VERSION 5.7 ;
BUSBITCHARS "[]" ;
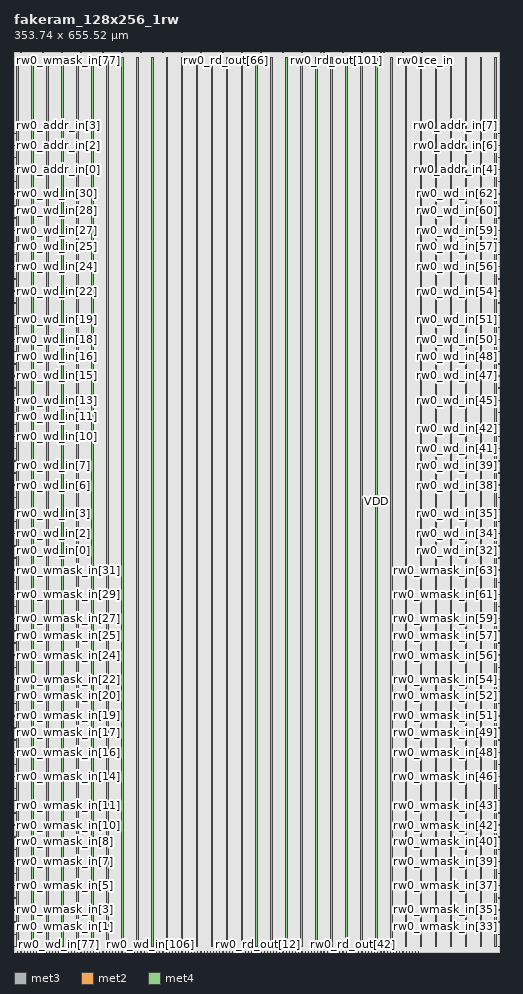
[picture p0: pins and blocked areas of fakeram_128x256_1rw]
MACRO fakeram_128x256_1rw
  FOREIGN fakeram_128x256_1rw 0 0 ;
  SYMMETRY X Y R90 ;
  SIZE 353.740 BY 655.520 ;
  CLASS BLOCK ;
  PIN rw0_wmask_in[0]
    DIRECTION INPUT ;
    USE SIGNAL ;
    SHAPE ABUTMENT ;
    PORT
      LAYER met3 ;
      RECT 0.000 3.930 0.900 4.230 ;
    END
  END rw0_wmask_in[0]
  PIN rw0_wmask_in[1]
    DIRECTION INPUT ;
    USE SIGNAL ;
    SHAPE ABUTMENT ;
    PORT
      LAYER met3 ;
      RECT 0.000 12.770 0.900 13.070 ;
    END
  END rw0_wmask_in[1]
  PIN rw0_wmask_in[2]
    DIRECTION INPUT ;
    USE SIGNAL ;
    SHAPE ABUTMENT ;
    PORT
      LAYER met3 ;
      RECT 0.000 21.610 0.900 21.910 ;
    END
  END rw0_wmask_in[2]
  PIN rw0_wmask_in[3]
    DIRECTION INPUT ;
    USE SIGNAL ;
    SHAPE ABUTMENT ;
    PORT
      LAYER met3 ;
      RECT 0.000 30.450 0.900 30.750 ;
    END
  END rw0_wmask_in[3]
  PIN rw0_wmask_in[4]
    DIRECTION INPUT ;
    USE SIGNAL ;
    SHAPE ABUTMENT ;
    PORT
      LAYER met3 ;
      RECT 0.000 39.290 0.900 39.590 ;
    END
  END rw0_wmask_in[4]
  PIN rw0_wmask_in[5]
    DIRECTION INPUT ;
    USE SIGNAL ;
    SHAPE ABUTMENT ;
    PORT
      LAYER met3 ;
      RECT 0.000 48.130 0.900 48.430 ;
    END
  END rw0_wmask_in[5]
  PIN rw0_wmask_in[6]
    DIRECTION INPUT ;
    USE SIGNAL ;
    SHAPE ABUTMENT ;
    PORT
      LAYER met3 ;
      RECT 0.000 56.970 0.900 57.270 ;
    END
  END rw0_wmask_in[6]
  PIN rw0_wmask_in[7]
    DIRECTION INPUT ;
    USE SIGNAL ;
    SHAPE ABUTMENT ;
    PORT
      LAYER met3 ;
      RECT 0.000 65.810 0.900 66.110 ;
    END
  END rw0_wmask_in[7]
  PIN rw0_wmask_in[8]
    DIRECTION INPUT ;
    USE SIGNAL ;
    SHAPE ABUTMENT ;
    PORT
      LAYER met3 ;
      RECT 0.000 74.650 0.900 74.950 ;
    END
  END rw0_wmask_in[8]
  PIN rw0_wmask_in[9]
    DIRECTION INPUT ;
    USE SIGNAL ;
    SHAPE ABUTMENT ;
    PORT
      LAYER met3 ;
      RECT 0.000 83.490 0.900 83.790 ;
    END
  END rw0_wmask_in[9]
  PIN rw0_wmask_in[10]
    DIRECTION INPUT ;
    USE SIGNAL ;
    SHAPE ABUTMENT ;
    PORT
      LAYER met3 ;
      RECT 0.000 92.330 0.900 92.630 ;
    END
  END rw0_wmask_in[10]
  PIN rw0_wmask_in[11]
    DIRECTION INPUT ;
    USE SIGNAL ;
    SHAPE ABUTMENT ;
    PORT
      LAYER met3 ;
      RECT 0.000 101.170 0.900 101.470 ;
    END
  END rw0_wmask_in[11]
  PIN rw0_wmask_in[12]
    DIRECTION INPUT ;
    USE SIGNAL ;
    SHAPE ABUTMENT ;
    PORT
      LAYER met3 ;
      RECT 0.000 110.010 0.900 110.310 ;
    END
  END rw0_wmask_in[12]
  PIN rw0_wmask_in[13]
    DIRECTION INPUT ;
    USE SIGNAL ;
    SHAPE ABUTMENT ;
    PORT
      LAYER met3 ;
      RECT 0.000 118.850 0.900 119.150 ;
    END
  END rw0_wmask_in[13]
  PIN rw0_wmask_in[14]
    DIRECTION INPUT ;
    USE SIGNAL ;
    SHAPE ABUTMENT ;
    PORT
      LAYER met3 ;
      RECT 0.000 127.690 0.900 127.990 ;
    END
  END rw0_wmask_in[14]
  PIN rw0_wmask_in[15]
    DIRECTION INPUT ;
    USE SIGNAL ;
    SHAPE ABUTMENT ;
    PORT
      LAYER met3 ;
      RECT 0.000 136.530 0.900 136.830 ;
    END
  END rw0_wmask_in[15]
  PIN rw0_wmask_in[16]
    DIRECTION INPUT ;
    USE SIGNAL ;
    SHAPE ABUTMENT ;
    PORT
      LAYER met3 ;
      RECT 0.000 145.370 0.900 145.670 ;
    END
  END rw0_wmask_in[16]
  PIN rw0_wmask_in[17]
    DIRECTION INPUT ;
    USE SIGNAL ;
    SHAPE ABUTMENT ;
    PORT
      LAYER met3 ;
      RECT 0.000 154.210 0.900 154.510 ;
    END
  END rw0_wmask_in[17]
  PIN rw0_wmask_in[18]
    DIRECTION INPUT ;
    USE SIGNAL ;
    SHAPE ABUTMENT ;
    PORT
      LAYER met3 ;
      RECT 0.000 163.050 0.900 163.350 ;
    END
  END rw0_wmask_in[18]
  PIN rw0_wmask_in[19]
    DIRECTION INPUT ;
    USE SIGNAL ;
    SHAPE ABUTMENT ;
    PORT
      LAYER met3 ;
      RECT 0.000 171.890 0.900 172.190 ;
    END
  END rw0_wmask_in[19]
  PIN rw0_wmask_in[20]
    DIRECTION INPUT ;
    USE SIGNAL ;
    SHAPE ABUTMENT ;
    PORT
      LAYER met3 ;
      RECT 0.000 180.730 0.900 181.030 ;
    END
  END rw0_wmask_in[20]
  PIN rw0_wmask_in[21]
    DIRECTION INPUT ;
    USE SIGNAL ;
    SHAPE ABUTMENT ;
    PORT
      LAYER met3 ;
      RECT 0.000 189.570 0.900 189.870 ;
    END
  END rw0_wmask_in[21]
  PIN rw0_wmask_in[22]
    DIRECTION INPUT ;
    USE SIGNAL ;
    SHAPE ABUTMENT ;
    PORT
      LAYER met3 ;
      RECT 0.000 198.410 0.900 198.710 ;
    END
  END rw0_wmask_in[22]
  PIN rw0_wmask_in[23]
    DIRECTION INPUT ;
    USE SIGNAL ;
    SHAPE ABUTMENT ;
    PORT
      LAYER met3 ;
      RECT 0.000 207.250 0.900 207.550 ;
    END
  END rw0_wmask_in[23]
  PIN rw0_wmask_in[24]
    DIRECTION INPUT ;
    USE SIGNAL ;
    SHAPE ABUTMENT ;
    PORT
      LAYER met3 ;
      RECT 0.000 216.090 0.900 216.390 ;
    END
  END rw0_wmask_in[24]
  PIN rw0_wmask_in[25]
    DIRECTION INPUT ;
    USE SIGNAL ;
    SHAPE ABUTMENT ;
    PORT
      LAYER met3 ;
      RECT 0.000 224.930 0.900 225.230 ;
    END
  END rw0_wmask_in[25]
  PIN rw0_wmask_in[26]
    DIRECTION INPUT ;
    USE SIGNAL ;
    SHAPE ABUTMENT ;
    PORT
      LAYER met3 ;
      RECT 0.000 233.770 0.900 234.070 ;
    END
  END rw0_wmask_in[26]
  PIN rw0_wmask_in[27]
    DIRECTION INPUT ;
    USE SIGNAL ;
    SHAPE ABUTMENT ;
    PORT
      LAYER met3 ;
      RECT 0.000 242.610 0.900 242.910 ;
    END
  END rw0_wmask_in[27]
  PIN rw0_wmask_in[28]
    DIRECTION INPUT ;
    USE SIGNAL ;
    SHAPE ABUTMENT ;
    PORT
      LAYER met3 ;
      RECT 0.000 251.450 0.900 251.750 ;
    END
  END rw0_wmask_in[28]
  PIN rw0_wmask_in[29]
    DIRECTION INPUT ;
    USE SIGNAL ;
    SHAPE ABUTMENT ;
    PORT
      LAYER met3 ;
      RECT 0.000 260.290 0.900 260.590 ;
    END
  END rw0_wmask_in[29]
  PIN rw0_wmask_in[30]
    DIRECTION INPUT ;
    USE SIGNAL ;
    SHAPE ABUTMENT ;
    PORT
      LAYER met3 ;
      RECT 0.000 269.130 0.900 269.430 ;
    END
  END rw0_wmask_in[30]
  PIN rw0_wmask_in[31]
    DIRECTION INPUT ;
    USE SIGNAL ;
    SHAPE ABUTMENT ;
    PORT
      LAYER met3 ;
      RECT 0.000 277.970 0.900 278.270 ;
    END
  END rw0_wmask_in[31]
  PIN rw0_wmask_in[32]
    DIRECTION INPUT ;
    USE SIGNAL ;
    SHAPE ABUTMENT ;
    PORT
      LAYER met3 ;
      RECT 352.840 3.930 353.740 4.230 ;
    END
  END rw0_wmask_in[32]
  PIN rw0_wmask_in[33]
    DIRECTION INPUT ;
    USE SIGNAL ;
    SHAPE ABUTMENT ;
    PORT
      LAYER met3 ;
      RECT 352.840 12.770 353.740 13.070 ;
    END
  END rw0_wmask_in[33]
  PIN rw0_wmask_in[34]
    DIRECTION INPUT ;
    USE SIGNAL ;
    SHAPE ABUTMENT ;
    PORT
      LAYER met3 ;
      RECT 352.840 21.610 353.740 21.910 ;
    END
  END rw0_wmask_in[34]
  PIN rw0_wmask_in[35]
    DIRECTION INPUT ;
    USE SIGNAL ;
    SHAPE ABUTMENT ;
    PORT
      LAYER met3 ;
      RECT 352.840 30.450 353.740 30.750 ;
    END
  END rw0_wmask_in[35]
  PIN rw0_wmask_in[36]
    DIRECTION INPUT ;
    USE SIGNAL ;
    SHAPE ABUTMENT ;
    PORT
      LAYER met3 ;
      RECT 352.840 39.290 353.740 39.590 ;
    END
  END rw0_wmask_in[36]
  PIN rw0_wmask_in[37]
    DIRECTION INPUT ;
    USE SIGNAL ;
    SHAPE ABUTMENT ;
    PORT
      LAYER met3 ;
      RECT 352.840 48.130 353.740 48.430 ;
    END
  END rw0_wmask_in[37]
  PIN rw0_wmask_in[38]
    DIRECTION INPUT ;
    USE SIGNAL ;
    SHAPE ABUTMENT ;
    PORT
      LAYER met3 ;
      RECT 352.840 56.970 353.740 57.270 ;
    END
  END rw0_wmask_in[38]
  PIN rw0_wmask_in[39]
    DIRECTION INPUT ;
    USE SIGNAL ;
    SHAPE ABUTMENT ;
    PORT
      LAYER met3 ;
      RECT 352.840 65.810 353.740 66.110 ;
    END
  END rw0_wmask_in[39]
  PIN rw0_wmask_in[40]
    DIRECTION INPUT ;
    USE SIGNAL ;
    SHAPE ABUTMENT ;
    PORT
      LAYER met3 ;
      RECT 352.840 74.650 353.740 74.950 ;
    END
  END rw0_wmask_in[40]
  PIN rw0_wmask_in[41]
    DIRECTION INPUT ;
    USE SIGNAL ;
    SHAPE ABUTMENT ;
    PORT
      LAYER met3 ;
      RECT 352.840 83.490 353.740 83.790 ;
    END
  END rw0_wmask_in[41]
  PIN rw0_wmask_in[42]
    DIRECTION INPUT ;
    USE SIGNAL ;
    SHAPE ABUTMENT ;
    PORT
      LAYER met3 ;
      RECT 352.840 92.330 353.740 92.630 ;
    END
  END rw0_wmask_in[42]
  PIN rw0_wmask_in[43]
    DIRECTION INPUT ;
    USE SIGNAL ;
    SHAPE ABUTMENT ;
    PORT
      LAYER met3 ;
      RECT 352.840 101.170 353.740 101.470 ;
    END
  END rw0_wmask_in[43]
  PIN rw0_wmask_in[44]
    DIRECTION INPUT ;
    USE SIGNAL ;
    SHAPE ABUTMENT ;
    PORT
      LAYER met3 ;
      RECT 352.840 110.010 353.740 110.310 ;
    END
  END rw0_wmask_in[44]
  PIN rw0_wmask_in[45]
    DIRECTION INPUT ;
    USE SIGNAL ;
    SHAPE ABUTMENT ;
    PORT
      LAYER met3 ;
      RECT 352.840 118.850 353.740 119.150 ;
    END
  END rw0_wmask_in[45]
  PIN rw0_wmask_in[46]
    DIRECTION INPUT ;
    USE SIGNAL ;
    SHAPE ABUTMENT ;
    PORT
      LAYER met3 ;
      RECT 352.840 127.690 353.740 127.990 ;
    END
  END rw0_wmask_in[46]
  PIN rw0_wmask_in[47]
    DIRECTION INPUT ;
    USE SIGNAL ;
    SHAPE ABUTMENT ;
    PORT
      LAYER met3 ;
      RECT 352.840 136.530 353.740 136.830 ;
    END
  END rw0_wmask_in[47]
  PIN rw0_wmask_in[48]
    DIRECTION INPUT ;
    USE SIGNAL ;
    SHAPE ABUTMENT ;
    PORT
      LAYER met3 ;
      RECT 352.840 145.370 353.740 145.670 ;
    END
  END rw0_wmask_in[48]
  PIN rw0_wmask_in[49]
    DIRECTION INPUT ;
    USE SIGNAL ;
    SHAPE ABUTMENT ;
    PORT
      LAYER met3 ;
      RECT 352.840 154.210 353.740 154.510 ;
    END
  END rw0_wmask_in[49]
  PIN rw0_wmask_in[50]
    DIRECTION INPUT ;
    USE SIGNAL ;
    SHAPE ABUTMENT ;
    PORT
      LAYER met3 ;
      RECT 352.840 163.050 353.740 163.350 ;
    END
  END rw0_wmask_in[50]
  PIN rw0_wmask_in[51]
    DIRECTION INPUT ;
    USE SIGNAL ;
    SHAPE ABUTMENT ;
    PORT
      LAYER met3 ;
      RECT 352.840 171.890 353.740 172.190 ;
    END
  END rw0_wmask_in[51]
  PIN rw0_wmask_in[52]
    DIRECTION INPUT ;
    USE SIGNAL ;
    SHAPE ABUTMENT ;
    PORT
      LAYER met3 ;
      RECT 352.840 180.730 353.740 181.030 ;
    END
  END rw0_wmask_in[52]
  PIN rw0_wmask_in[53]
    DIRECTION INPUT ;
    USE SIGNAL ;
    SHAPE ABUTMENT ;
    PORT
      LAYER met3 ;
      RECT 352.840 189.570 353.740 189.870 ;
    END
  END rw0_wmask_in[53]
  PIN rw0_wmask_in[54]
    DIRECTION INPUT ;
    USE SIGNAL ;
    SHAPE ABUTMENT ;
    PORT
      LAYER met3 ;
      RECT 352.840 198.410 353.740 198.710 ;
    END
  END rw0_wmask_in[54]
  PIN rw0_wmask_in[55]
    DIRECTION INPUT ;
    USE SIGNAL ;
    SHAPE ABUTMENT ;
    PORT
      LAYER met3 ;
      RECT 352.840 207.250 353.740 207.550 ;
    END
  END rw0_wmask_in[55]
  PIN rw0_wmask_in[56]
    DIRECTION INPUT ;
    USE SIGNAL ;
    SHAPE ABUTMENT ;
    PORT
      LAYER met3 ;
      RECT 352.840 216.090 353.740 216.390 ;
    END
  END rw0_wmask_in[56]
  PIN rw0_wmask_in[57]
    DIRECTION INPUT ;
    USE SIGNAL ;
    SHAPE ABUTMENT ;
    PORT
      LAYER met3 ;
      RECT 352.840 224.930 353.740 225.230 ;
    END
  END rw0_wmask_in[57]
  PIN rw0_wmask_in[58]
    DIRECTION INPUT ;
    USE SIGNAL ;
    SHAPE ABUTMENT ;
    PORT
      LAYER met3 ;
      RECT 352.840 233.770 353.740 234.070 ;
    END
  END rw0_wmask_in[58]
  PIN rw0_wmask_in[59]
    DIRECTION INPUT ;
    USE SIGNAL ;
    SHAPE ABUTMENT ;
    PORT
      LAYER met3 ;
      RECT 352.840 242.610 353.740 242.910 ;
    END
  END rw0_wmask_in[59]
  PIN rw0_wmask_in[60]
    DIRECTION INPUT ;
    USE SIGNAL ;
    SHAPE ABUTMENT ;
    PORT
      LAYER met3 ;
      RECT 352.840 251.450 353.740 251.750 ;
    END
  END rw0_wmask_in[60]
  PIN rw0_wmask_in[61]
    DIRECTION INPUT ;
    USE SIGNAL ;
    SHAPE ABUTMENT ;
    PORT
      LAYER met3 ;
      RECT 352.840 260.290 353.740 260.590 ;
    END
  END rw0_wmask_in[61]
  PIN rw0_wmask_in[62]
    DIRECTION INPUT ;
    USE SIGNAL ;
    SHAPE ABUTMENT ;
    PORT
      LAYER met3 ;
      RECT 352.840 269.130 353.740 269.430 ;
    END
  END rw0_wmask_in[62]
  PIN rw0_wmask_in[63]
    DIRECTION INPUT ;
    USE SIGNAL ;
    SHAPE ABUTMENT ;
    PORT
      LAYER met3 ;
      RECT 352.840 277.970 353.740 278.270 ;
    END
  END rw0_wmask_in[63]
  PIN rw0_wmask_in[64]
    DIRECTION INPUT ;
    USE SIGNAL ;
    SHAPE ABUTMENT ;
    PORT
      LAYER met2 ;
      RECT 2.690 655.100 2.830 655.520 ;
    END
  END rw0_wmask_in[64]
  PIN rw0_wmask_in[65]
    DIRECTION INPUT ;
    USE SIGNAL ;
    SHAPE ABUTMENT ;
    PORT
      LAYER met2 ;
      RECT 4.990 655.100 5.130 655.520 ;
    END
  END rw0_wmask_in[65]
  PIN rw0_wmask_in[66]
    DIRECTION INPUT ;
    USE SIGNAL ;
    SHAPE ABUTMENT ;
    PORT
      LAYER met2 ;
      RECT 7.290 655.100 7.430 655.520 ;
    END
  END rw0_wmask_in[66]
  PIN rw0_wmask_in[67]
    DIRECTION INPUT ;
    USE SIGNAL ;
    SHAPE ABUTMENT ;
    PORT
      LAYER met2 ;
      RECT 9.590 655.100 9.730 655.520 ;
    END
  END rw0_wmask_in[67]
  PIN rw0_wmask_in[68]
    DIRECTION INPUT ;
    USE SIGNAL ;
    SHAPE ABUTMENT ;
    PORT
      LAYER met2 ;
      RECT 11.890 655.100 12.030 655.520 ;
    END
  END rw0_wmask_in[68]
  PIN rw0_wmask_in[69]
    DIRECTION INPUT ;
    USE SIGNAL ;
    SHAPE ABUTMENT ;
    PORT
      LAYER met2 ;
      RECT 14.190 655.100 14.330 655.520 ;
    END
  END rw0_wmask_in[69]
  PIN rw0_wmask_in[70]
    DIRECTION INPUT ;
    USE SIGNAL ;
    SHAPE ABUTMENT ;
    PORT
      LAYER met2 ;
      RECT 16.490 655.100 16.630 655.520 ;
    END
  END rw0_wmask_in[70]
  PIN rw0_wmask_in[71]
    DIRECTION INPUT ;
    USE SIGNAL ;
    SHAPE ABUTMENT ;
    PORT
      LAYER met2 ;
      RECT 18.790 655.100 18.930 655.520 ;
    END
  END rw0_wmask_in[71]
  PIN rw0_wmask_in[72]
    DIRECTION INPUT ;
    USE SIGNAL ;
    SHAPE ABUTMENT ;
    PORT
      LAYER met2 ;
      RECT 21.090 655.100 21.230 655.520 ;
    END
  END rw0_wmask_in[72]
  PIN rw0_wmask_in[73]
    DIRECTION INPUT ;
    USE SIGNAL ;
    SHAPE ABUTMENT ;
    PORT
      LAYER met2 ;
      RECT 23.390 655.100 23.530 655.520 ;
    END
  END rw0_wmask_in[73]
  PIN rw0_wmask_in[74]
    DIRECTION INPUT ;
    USE SIGNAL ;
    SHAPE ABUTMENT ;
    PORT
      LAYER met2 ;
      RECT 25.690 655.100 25.830 655.520 ;
    END
  END rw0_wmask_in[74]
  PIN rw0_wmask_in[75]
    DIRECTION INPUT ;
    USE SIGNAL ;
    SHAPE ABUTMENT ;
    PORT
      LAYER met2 ;
      RECT 27.990 655.100 28.130 655.520 ;
    END
  END rw0_wmask_in[75]
  PIN rw0_wmask_in[76]
    DIRECTION INPUT ;
    USE SIGNAL ;
    SHAPE ABUTMENT ;
    PORT
      LAYER met2 ;
      RECT 30.290 655.100 30.430 655.520 ;
    END
  END rw0_wmask_in[76]
  PIN rw0_wmask_in[77]
    DIRECTION INPUT ;
    USE SIGNAL ;
    SHAPE ABUTMENT ;
    PORT
      LAYER met2 ;
      RECT 32.590 655.100 32.730 655.520 ;
    END
  END rw0_wmask_in[77]
  PIN rw0_wmask_in[78]
    DIRECTION INPUT ;
    USE SIGNAL ;
    SHAPE ABUTMENT ;
    PORT
      LAYER met2 ;
      RECT 34.890 655.100 35.030 655.520 ;
    END
  END rw0_wmask_in[78]
  PIN rw0_wmask_in[79]
    DIRECTION INPUT ;
    USE SIGNAL ;
    SHAPE ABUTMENT ;
    PORT
      LAYER met2 ;
      RECT 37.190 655.100 37.330 655.520 ;
    END
  END rw0_wmask_in[79]
  PIN rw0_wmask_in[80]
    DIRECTION INPUT ;
    USE SIGNAL ;
    SHAPE ABUTMENT ;
    PORT
      LAYER met2 ;
      RECT 39.490 655.100 39.630 655.520 ;
    END
  END rw0_wmask_in[80]
  PIN rw0_wmask_in[81]
    DIRECTION INPUT ;
    USE SIGNAL ;
    SHAPE ABUTMENT ;
    PORT
      LAYER met2 ;
      RECT 41.790 655.100 41.930 655.520 ;
    END
  END rw0_wmask_in[81]
  PIN rw0_wmask_in[82]
    DIRECTION INPUT ;
    USE SIGNAL ;
    SHAPE ABUTMENT ;
    PORT
      LAYER met2 ;
      RECT 44.090 655.100 44.230 655.520 ;
    END
  END rw0_wmask_in[82]
  PIN rw0_wmask_in[83]
    DIRECTION INPUT ;
    USE SIGNAL ;
    SHAPE ABUTMENT ;
    PORT
      LAYER met2 ;
      RECT 46.390 655.100 46.530 655.520 ;
    END
  END rw0_wmask_in[83]
  PIN rw0_wmask_in[84]
    DIRECTION INPUT ;
    USE SIGNAL ;
    SHAPE ABUTMENT ;
    PORT
      LAYER met2 ;
      RECT 48.690 655.100 48.830 655.520 ;
    END
  END rw0_wmask_in[84]
  PIN rw0_wmask_in[85]
    DIRECTION INPUT ;
    USE SIGNAL ;
    SHAPE ABUTMENT ;
    PORT
      LAYER met2 ;
      RECT 50.990 655.100 51.130 655.520 ;
    END
  END rw0_wmask_in[85]
  PIN rw0_wmask_in[86]
    DIRECTION INPUT ;
    USE SIGNAL ;
    SHAPE ABUTMENT ;
    PORT
      LAYER met2 ;
      RECT 53.290 655.100 53.430 655.520 ;
    END
  END rw0_wmask_in[86]
  PIN rw0_wmask_in[87]
    DIRECTION INPUT ;
    USE SIGNAL ;
    SHAPE ABUTMENT ;
    PORT
      LAYER met2 ;
      RECT 55.590 655.100 55.730 655.520 ;
    END
  END rw0_wmask_in[87]
  PIN rw0_wmask_in[88]
    DIRECTION INPUT ;
    USE SIGNAL ;
    SHAPE ABUTMENT ;
    PORT
      LAYER met2 ;
      RECT 57.890 655.100 58.030 655.520 ;
    END
  END rw0_wmask_in[88]
  PIN rw0_wmask_in[89]
    DIRECTION INPUT ;
    USE SIGNAL ;
    SHAPE ABUTMENT ;
    PORT
      LAYER met2 ;
      RECT 60.190 655.100 60.330 655.520 ;
    END
  END rw0_wmask_in[89]
  PIN rw0_wmask_in[90]
    DIRECTION INPUT ;
    USE SIGNAL ;
    SHAPE ABUTMENT ;
    PORT
      LAYER met2 ;
      RECT 62.490 655.100 62.630 655.520 ;
    END
  END rw0_wmask_in[90]
  PIN rw0_wmask_in[91]
    DIRECTION INPUT ;
    USE SIGNAL ;
    SHAPE ABUTMENT ;
    PORT
      LAYER met2 ;
      RECT 64.790 655.100 64.930 655.520 ;
    END
  END rw0_wmask_in[91]
  PIN rw0_wmask_in[92]
    DIRECTION INPUT ;
    USE SIGNAL ;
    SHAPE ABUTMENT ;
    PORT
      LAYER met2 ;
      RECT 67.090 655.100 67.230 655.520 ;
    END
  END rw0_wmask_in[92]
  PIN rw0_wmask_in[93]
    DIRECTION INPUT ;
    USE SIGNAL ;
    SHAPE ABUTMENT ;
    PORT
      LAYER met2 ;
      RECT 69.390 655.100 69.530 655.520 ;
    END
  END rw0_wmask_in[93]
  PIN rw0_wmask_in[94]
    DIRECTION INPUT ;
    USE SIGNAL ;
    SHAPE ABUTMENT ;
    PORT
      LAYER met2 ;
      RECT 71.690 655.100 71.830 655.520 ;
    END
  END rw0_wmask_in[94]
  PIN rw0_wmask_in[95]
    DIRECTION INPUT ;
    USE SIGNAL ;
    SHAPE ABUTMENT ;
    PORT
      LAYER met2 ;
      RECT 73.990 655.100 74.130 655.520 ;
    END
  END rw0_wmask_in[95]
  PIN rw0_wmask_in[96]
    DIRECTION INPUT ;
    USE SIGNAL ;
    SHAPE ABUTMENT ;
    PORT
      LAYER met2 ;
      RECT 76.290 655.100 76.430 655.520 ;
    END
  END rw0_wmask_in[96]
  PIN rw0_wmask_in[97]
    DIRECTION INPUT ;
    USE SIGNAL ;
    SHAPE ABUTMENT ;
    PORT
      LAYER met2 ;
      RECT 78.590 655.100 78.730 655.520 ;
    END
  END rw0_wmask_in[97]
  PIN rw0_wmask_in[98]
    DIRECTION INPUT ;
    USE SIGNAL ;
    SHAPE ABUTMENT ;
    PORT
      LAYER met2 ;
      RECT 80.890 655.100 81.030 655.520 ;
    END
  END rw0_wmask_in[98]
  PIN rw0_wmask_in[99]
    DIRECTION INPUT ;
    USE SIGNAL ;
    SHAPE ABUTMENT ;
    PORT
      LAYER met2 ;
      RECT 83.190 655.100 83.330 655.520 ;
    END
  END rw0_wmask_in[99]
  PIN rw0_wmask_in[100]
    DIRECTION INPUT ;
    USE SIGNAL ;
    SHAPE ABUTMENT ;
    PORT
      LAYER met2 ;
      RECT 85.490 655.100 85.630 655.520 ;
    END
  END rw0_wmask_in[100]
  PIN rw0_wmask_in[101]
    DIRECTION INPUT ;
    USE SIGNAL ;
    SHAPE ABUTMENT ;
    PORT
      LAYER met2 ;
      RECT 87.790 655.100 87.930 655.520 ;
    END
  END rw0_wmask_in[101]
  PIN rw0_wmask_in[102]
    DIRECTION INPUT ;
    USE SIGNAL ;
    SHAPE ABUTMENT ;
    PORT
      LAYER met2 ;
      RECT 90.090 655.100 90.230 655.520 ;
    END
  END rw0_wmask_in[102]
  PIN rw0_wmask_in[103]
    DIRECTION INPUT ;
    USE SIGNAL ;
    SHAPE ABUTMENT ;
    PORT
      LAYER met2 ;
      RECT 92.390 655.100 92.530 655.520 ;
    END
  END rw0_wmask_in[103]
  PIN rw0_wmask_in[104]
    DIRECTION INPUT ;
    USE SIGNAL ;
    SHAPE ABUTMENT ;
    PORT
      LAYER met2 ;
      RECT 94.690 655.100 94.830 655.520 ;
    END
  END rw0_wmask_in[104]
  PIN rw0_wmask_in[105]
    DIRECTION INPUT ;
    USE SIGNAL ;
    SHAPE ABUTMENT ;
    PORT
      LAYER met2 ;
      RECT 96.990 655.100 97.130 655.520 ;
    END
  END rw0_wmask_in[105]
  PIN rw0_wmask_in[106]
    DIRECTION INPUT ;
    USE SIGNAL ;
    SHAPE ABUTMENT ;
    PORT
      LAYER met2 ;
      RECT 99.290 655.100 99.430 655.520 ;
    END
  END rw0_wmask_in[106]
  PIN rw0_wmask_in[107]
    DIRECTION INPUT ;
    USE SIGNAL ;
    SHAPE ABUTMENT ;
    PORT
      LAYER met2 ;
      RECT 101.590 655.100 101.730 655.520 ;
    END
  END rw0_wmask_in[107]
  PIN rw0_wmask_in[108]
    DIRECTION INPUT ;
    USE SIGNAL ;
    SHAPE ABUTMENT ;
    PORT
      LAYER met2 ;
      RECT 103.890 655.100 104.030 655.520 ;
    END
  END rw0_wmask_in[108]
  PIN rw0_wmask_in[109]
    DIRECTION INPUT ;
    USE SIGNAL ;
    SHAPE ABUTMENT ;
    PORT
      LAYER met2 ;
      RECT 106.190 655.100 106.330 655.520 ;
    END
  END rw0_wmask_in[109]
  PIN rw0_wmask_in[110]
    DIRECTION INPUT ;
    USE SIGNAL ;
    SHAPE ABUTMENT ;
    PORT
      LAYER met2 ;
      RECT 108.490 655.100 108.630 655.520 ;
    END
  END rw0_wmask_in[110]
  PIN rw0_wmask_in[111]
    DIRECTION INPUT ;
    USE SIGNAL ;
    SHAPE ABUTMENT ;
    PORT
      LAYER met2 ;
      RECT 110.790 655.100 110.930 655.520 ;
    END
  END rw0_wmask_in[111]
  PIN rw0_wmask_in[112]
    DIRECTION INPUT ;
    USE SIGNAL ;
    SHAPE ABUTMENT ;
    PORT
      LAYER met2 ;
      RECT 113.090 655.100 113.230 655.520 ;
    END
  END rw0_wmask_in[112]
  PIN rw0_wmask_in[113]
    DIRECTION INPUT ;
    USE SIGNAL ;
    SHAPE ABUTMENT ;
    PORT
      LAYER met2 ;
      RECT 115.390 655.100 115.530 655.520 ;
    END
  END rw0_wmask_in[113]
  PIN rw0_wmask_in[114]
    DIRECTION INPUT ;
    USE SIGNAL ;
    SHAPE ABUTMENT ;
    PORT
      LAYER met2 ;
      RECT 117.690 655.100 117.830 655.520 ;
    END
  END rw0_wmask_in[114]
  PIN rw0_wmask_in[115]
    DIRECTION INPUT ;
    USE SIGNAL ;
    SHAPE ABUTMENT ;
    PORT
      LAYER met2 ;
      RECT 119.990 655.100 120.130 655.520 ;
    END
  END rw0_wmask_in[115]
  PIN rw0_wmask_in[116]
    DIRECTION INPUT ;
    USE SIGNAL ;
    SHAPE ABUTMENT ;
    PORT
      LAYER met2 ;
      RECT 122.290 655.100 122.430 655.520 ;
    END
  END rw0_wmask_in[116]
  PIN rw0_wmask_in[117]
    DIRECTION INPUT ;
    USE SIGNAL ;
    SHAPE ABUTMENT ;
    PORT
      LAYER met2 ;
      RECT 124.590 655.100 124.730 655.520 ;
    END
  END rw0_wmask_in[117]
  PIN rw0_wmask_in[118]
    DIRECTION INPUT ;
    USE SIGNAL ;
    SHAPE ABUTMENT ;
    PORT
      LAYER met2 ;
      RECT 126.890 655.100 127.030 655.520 ;
    END
  END rw0_wmask_in[118]
  PIN rw0_wmask_in[119]
    DIRECTION INPUT ;
    USE SIGNAL ;
    SHAPE ABUTMENT ;
    PORT
      LAYER met2 ;
      RECT 129.190 655.100 129.330 655.520 ;
    END
  END rw0_wmask_in[119]
  PIN rw0_wmask_in[120]
    DIRECTION INPUT ;
    USE SIGNAL ;
    SHAPE ABUTMENT ;
    PORT
      LAYER met2 ;
      RECT 131.490 655.100 131.630 655.520 ;
    END
  END rw0_wmask_in[120]
  PIN rw0_wmask_in[121]
    DIRECTION INPUT ;
    USE SIGNAL ;
    SHAPE ABUTMENT ;
    PORT
      LAYER met2 ;
      RECT 133.790 655.100 133.930 655.520 ;
    END
  END rw0_wmask_in[121]
  PIN rw0_wmask_in[122]
    DIRECTION INPUT ;
    USE SIGNAL ;
    SHAPE ABUTMENT ;
    PORT
      LAYER met2 ;
      RECT 136.090 655.100 136.230 655.520 ;
    END
  END rw0_wmask_in[122]
  PIN rw0_wmask_in[123]
    DIRECTION INPUT ;
    USE SIGNAL ;
    SHAPE ABUTMENT ;
    PORT
      LAYER met2 ;
      RECT 138.390 655.100 138.530 655.520 ;
    END
  END rw0_wmask_in[123]
  PIN rw0_wmask_in[124]
    DIRECTION INPUT ;
    USE SIGNAL ;
    SHAPE ABUTMENT ;
    PORT
      LAYER met2 ;
      RECT 140.690 655.100 140.830 655.520 ;
    END
  END rw0_wmask_in[124]
  PIN rw0_wmask_in[125]
    DIRECTION INPUT ;
    USE SIGNAL ;
    SHAPE ABUTMENT ;
    PORT
      LAYER met2 ;
      RECT 142.990 655.100 143.130 655.520 ;
    END
  END rw0_wmask_in[125]
  PIN rw0_wmask_in[126]
    DIRECTION INPUT ;
    USE SIGNAL ;
    SHAPE ABUTMENT ;
    PORT
      LAYER met2 ;
      RECT 145.290 655.100 145.430 655.520 ;
    END
  END rw0_wmask_in[126]
  PIN rw0_wmask_in[127]
    DIRECTION INPUT ;
    USE SIGNAL ;
    SHAPE ABUTMENT ;
    PORT
      LAYER met2 ;
      RECT 147.590 655.100 147.730 655.520 ;
    END
  END rw0_wmask_in[127]
  PIN rw0_wd_in[0]
    DIRECTION INPUT ;
    USE SIGNAL ;
    SHAPE ABUTMENT ;
    PORT
      LAYER met3 ;
      RECT 0.000 286.810 0.900 287.110 ;
    END
  END rw0_wd_in[0]
  PIN rw0_wd_in[1]
    DIRECTION INPUT ;
    USE SIGNAL ;
    SHAPE ABUTMENT ;
    PORT
      LAYER met3 ;
      RECT 0.000 295.650 0.900 295.950 ;
    END
  END rw0_wd_in[1]
  PIN rw0_wd_in[2]
    DIRECTION INPUT ;
    USE SIGNAL ;
    SHAPE ABUTMENT ;
    PORT
      LAYER met3 ;
      RECT 0.000 304.490 0.900 304.790 ;
    END
  END rw0_wd_in[2]
  PIN rw0_wd_in[3]
    DIRECTION INPUT ;
    USE SIGNAL ;
    SHAPE ABUTMENT ;
    PORT
      LAYER met3 ;
      RECT 0.000 313.330 0.900 313.630 ;
    END
  END rw0_wd_in[3]
  PIN rw0_wd_in[4]
    DIRECTION INPUT ;
    USE SIGNAL ;
    SHAPE ABUTMENT ;
    PORT
      LAYER met3 ;
      RECT 0.000 322.170 0.900 322.470 ;
    END
  END rw0_wd_in[4]
  PIN rw0_wd_in[5]
    DIRECTION INPUT ;
    USE SIGNAL ;
    SHAPE ABUTMENT ;
    PORT
      LAYER met3 ;
      RECT 0.000 331.010 0.900 331.310 ;
    END
  END rw0_wd_in[5]
  PIN rw0_wd_in[6]
    DIRECTION INPUT ;
    USE SIGNAL ;
    SHAPE ABUTMENT ;
    PORT
      LAYER met3 ;
      RECT 0.000 339.850 0.900 340.150 ;
    END
  END rw0_wd_in[6]
  PIN rw0_wd_in[7]
    DIRECTION INPUT ;
    USE SIGNAL ;
    SHAPE ABUTMENT ;
    PORT
      LAYER met3 ;
      RECT 0.000 348.690 0.900 348.990 ;
    END
  END rw0_wd_in[7]
  PIN rw0_wd_in[8]
    DIRECTION INPUT ;
    USE SIGNAL ;
    SHAPE ABUTMENT ;
    PORT
      LAYER met3 ;
      RECT 0.000 357.530 0.900 357.830 ;
    END
  END rw0_wd_in[8]
  PIN rw0_wd_in[9]
    DIRECTION INPUT ;
    USE SIGNAL ;
    SHAPE ABUTMENT ;
    PORT
      LAYER met3 ;
      RECT 0.000 366.370 0.900 366.670 ;
    END
  END rw0_wd_in[9]
  PIN rw0_wd_in[10]
    DIRECTION INPUT ;
    USE SIGNAL ;
    SHAPE ABUTMENT ;
    PORT
      LAYER met3 ;
      RECT 0.000 375.210 0.900 375.510 ;
    END
  END rw0_wd_in[10]
  PIN rw0_wd_in[11]
    DIRECTION INPUT ;
    USE SIGNAL ;
    SHAPE ABUTMENT ;
    PORT
      LAYER met3 ;
      RECT 0.000 384.050 0.900 384.350 ;
    END
  END rw0_wd_in[11]
  PIN rw0_wd_in[12]
    DIRECTION INPUT ;
    USE SIGNAL ;
    SHAPE ABUTMENT ;
    PORT
      LAYER met3 ;
      RECT 0.000 392.890 0.900 393.190 ;
    END
  END rw0_wd_in[12]
  PIN rw0_wd_in[13]
    DIRECTION INPUT ;
    USE SIGNAL ;
    SHAPE ABUTMENT ;
    PORT
      LAYER met3 ;
      RECT 0.000 401.730 0.900 402.030 ;
    END
  END rw0_wd_in[13]
  PIN rw0_wd_in[14]
    DIRECTION INPUT ;
    USE SIGNAL ;
    SHAPE ABUTMENT ;
    PORT
      LAYER met3 ;
      RECT 0.000 410.570 0.900 410.870 ;
    END
  END rw0_wd_in[14]
  PIN rw0_wd_in[15]
    DIRECTION INPUT ;
    USE SIGNAL ;
    SHAPE ABUTMENT ;
    PORT
      LAYER met3 ;
      RECT 0.000 419.410 0.900 419.710 ;
    END
  END rw0_wd_in[15]
  PIN rw0_wd_in[16]
    DIRECTION INPUT ;
    USE SIGNAL ;
    SHAPE ABUTMENT ;
    PORT
      LAYER met3 ;
      RECT 0.000 428.250 0.900 428.550 ;
    END
  END rw0_wd_in[16]
  PIN rw0_wd_in[17]
    DIRECTION INPUT ;
    USE SIGNAL ;
    SHAPE ABUTMENT ;
    PORT
      LAYER met3 ;
      RECT 0.000 437.090 0.900 437.390 ;
    END
  END rw0_wd_in[17]
  PIN rw0_wd_in[18]
    DIRECTION INPUT ;
    USE SIGNAL ;
    SHAPE ABUTMENT ;
    PORT
      LAYER met3 ;
      RECT 0.000 445.930 0.900 446.230 ;
    END
  END rw0_wd_in[18]
  PIN rw0_wd_in[19]
    DIRECTION INPUT ;
    USE SIGNAL ;
    SHAPE ABUTMENT ;
    PORT
      LAYER met3 ;
      RECT 0.000 454.770 0.900 455.070 ;
    END
  END rw0_wd_in[19]
  PIN rw0_wd_in[20]
    DIRECTION INPUT ;
    USE SIGNAL ;
    SHAPE ABUTMENT ;
    PORT
      LAYER met3 ;
      RECT 0.000 463.610 0.900 463.910 ;
    END
  END rw0_wd_in[20]
  PIN rw0_wd_in[21]
    DIRECTION INPUT ;
    USE SIGNAL ;
    SHAPE ABUTMENT ;
    PORT
      LAYER met3 ;
      RECT 0.000 472.450 0.900 472.750 ;
    END
  END rw0_wd_in[21]
  PIN rw0_wd_in[22]
    DIRECTION INPUT ;
    USE SIGNAL ;
    SHAPE ABUTMENT ;
    PORT
      LAYER met3 ;
      RECT 0.000 481.290 0.900 481.590 ;
    END
  END rw0_wd_in[22]
  PIN rw0_wd_in[23]
    DIRECTION INPUT ;
    USE SIGNAL ;
    SHAPE ABUTMENT ;
    PORT
      LAYER met3 ;
      RECT 0.000 490.130 0.900 490.430 ;
    END
  END rw0_wd_in[23]
  PIN rw0_wd_in[24]
    DIRECTION INPUT ;
    USE SIGNAL ;
    SHAPE ABUTMENT ;
    PORT
      LAYER met3 ;
      RECT 0.000 498.970 0.900 499.270 ;
    END
  END rw0_wd_in[24]
  PIN rw0_wd_in[25]
    DIRECTION INPUT ;
    USE SIGNAL ;
    SHAPE ABUTMENT ;
    PORT
      LAYER met3 ;
      RECT 0.000 507.810 0.900 508.110 ;
    END
  END rw0_wd_in[25]
  PIN rw0_wd_in[26]
    DIRECTION INPUT ;
    USE SIGNAL ;
    SHAPE ABUTMENT ;
    PORT
      LAYER met3 ;
      RECT 0.000 516.650 0.900 516.950 ;
    END
  END rw0_wd_in[26]
  PIN rw0_wd_in[27]
    DIRECTION INPUT ;
    USE SIGNAL ;
    SHAPE ABUTMENT ;
    PORT
      LAYER met3 ;
      RECT 0.000 525.490 0.900 525.790 ;
    END
  END rw0_wd_in[27]
  PIN rw0_wd_in[28]
    DIRECTION INPUT ;
    USE SIGNAL ;
    SHAPE ABUTMENT ;
    PORT
      LAYER met3 ;
      RECT 0.000 534.330 0.900 534.630 ;
    END
  END rw0_wd_in[28]
  PIN rw0_wd_in[29]
    DIRECTION INPUT ;
    USE SIGNAL ;
    SHAPE ABUTMENT ;
    PORT
      LAYER met3 ;
      RECT 0.000 543.170 0.900 543.470 ;
    END
  END rw0_wd_in[29]
  PIN rw0_wd_in[30]
    DIRECTION INPUT ;
    USE SIGNAL ;
    SHAPE ABUTMENT ;
    PORT
      LAYER met3 ;
      RECT 0.000 552.010 0.900 552.310 ;
    END
  END rw0_wd_in[30]
  PIN rw0_wd_in[31]
    DIRECTION INPUT ;
    USE SIGNAL ;
    SHAPE ABUTMENT ;
    PORT
      LAYER met3 ;
      RECT 0.000 560.850 0.900 561.150 ;
    END
  END rw0_wd_in[31]
  PIN rw0_wd_in[32]
    DIRECTION INPUT ;
    USE SIGNAL ;
    SHAPE ABUTMENT ;
    PORT
      LAYER met3 ;
      RECT 352.840 286.810 353.740 287.110 ;
    END
  END rw0_wd_in[32]
  PIN rw0_wd_in[33]
    DIRECTION INPUT ;
    USE SIGNAL ;
    SHAPE ABUTMENT ;
    PORT
      LAYER met3 ;
      RECT 352.840 295.650 353.740 295.950 ;
    END
  END rw0_wd_in[33]
  PIN rw0_wd_in[34]
    DIRECTION INPUT ;
    USE SIGNAL ;
    SHAPE ABUTMENT ;
    PORT
      LAYER met3 ;
      RECT 352.840 304.490 353.740 304.790 ;
    END
  END rw0_wd_in[34]
  PIN rw0_wd_in[35]
    DIRECTION INPUT ;
    USE SIGNAL ;
    SHAPE ABUTMENT ;
    PORT
      LAYER met3 ;
      RECT 352.840 313.330 353.740 313.630 ;
    END
  END rw0_wd_in[35]
  PIN rw0_wd_in[36]
    DIRECTION INPUT ;
    USE SIGNAL ;
    SHAPE ABUTMENT ;
    PORT
      LAYER met3 ;
      RECT 352.840 322.170 353.740 322.470 ;
    END
  END rw0_wd_in[36]
  PIN rw0_wd_in[37]
    DIRECTION INPUT ;
    USE SIGNAL ;
    SHAPE ABUTMENT ;
    PORT
      LAYER met3 ;
      RECT 352.840 331.010 353.740 331.310 ;
    END
  END rw0_wd_in[37]
  PIN rw0_wd_in[38]
    DIRECTION INPUT ;
    USE SIGNAL ;
    SHAPE ABUTMENT ;
    PORT
      LAYER met3 ;
      RECT 352.840 339.850 353.740 340.150 ;
    END
  END rw0_wd_in[38]
  PIN rw0_wd_in[39]
    DIRECTION INPUT ;
    USE SIGNAL ;
    SHAPE ABUTMENT ;
    PORT
      LAYER met3 ;
      RECT 352.840 348.690 353.740 348.990 ;
    END
  END rw0_wd_in[39]
  PIN rw0_wd_in[40]
    DIRECTION INPUT ;
    USE SIGNAL ;
    SHAPE ABUTMENT ;
    PORT
      LAYER met3 ;
      RECT 352.840 357.530 353.740 357.830 ;
    END
  END rw0_wd_in[40]
  PIN rw0_wd_in[41]
    DIRECTION INPUT ;
    USE SIGNAL ;
    SHAPE ABUTMENT ;
    PORT
      LAYER met3 ;
      RECT 352.840 366.370 353.740 366.670 ;
    END
  END rw0_wd_in[41]
  PIN rw0_wd_in[42]
    DIRECTION INPUT ;
    USE SIGNAL ;
    SHAPE ABUTMENT ;
    PORT
      LAYER met3 ;
      RECT 352.840 375.210 353.740 375.510 ;
    END
  END rw0_wd_in[42]
  PIN rw0_wd_in[43]
    DIRECTION INPUT ;
    USE SIGNAL ;
    SHAPE ABUTMENT ;
    PORT
      LAYER met3 ;
      RECT 352.840 384.050 353.740 384.350 ;
    END
  END rw0_wd_in[43]
  PIN rw0_wd_in[44]
    DIRECTION INPUT ;
    USE SIGNAL ;
    SHAPE ABUTMENT ;
    PORT
      LAYER met3 ;
      RECT 352.840 392.890 353.740 393.190 ;
    END
  END rw0_wd_in[44]
  PIN rw0_wd_in[45]
    DIRECTION INPUT ;
    USE SIGNAL ;
    SHAPE ABUTMENT ;
    PORT
      LAYER met3 ;
      RECT 352.840 401.730 353.740 402.030 ;
    END
  END rw0_wd_in[45]
  PIN rw0_wd_in[46]
    DIRECTION INPUT ;
    USE SIGNAL ;
    SHAPE ABUTMENT ;
    PORT
      LAYER met3 ;
      RECT 352.840 410.570 353.740 410.870 ;
    END
  END rw0_wd_in[46]
  PIN rw0_wd_in[47]
    DIRECTION INPUT ;
    USE SIGNAL ;
    SHAPE ABUTMENT ;
    PORT
      LAYER met3 ;
      RECT 352.840 419.410 353.740 419.710 ;
    END
  END rw0_wd_in[47]
  PIN rw0_wd_in[48]
    DIRECTION INPUT ;
    USE SIGNAL ;
    SHAPE ABUTMENT ;
    PORT
      LAYER met3 ;
      RECT 352.840 428.250 353.740 428.550 ;
    END
  END rw0_wd_in[48]
  PIN rw0_wd_in[49]
    DIRECTION INPUT ;
    USE SIGNAL ;
    SHAPE ABUTMENT ;
    PORT
      LAYER met3 ;
      RECT 352.840 437.090 353.740 437.390 ;
    END
  END rw0_wd_in[49]
  PIN rw0_wd_in[50]
    DIRECTION INPUT ;
    USE SIGNAL ;
    SHAPE ABUTMENT ;
    PORT
      LAYER met3 ;
      RECT 352.840 445.930 353.740 446.230 ;
    END
  END rw0_wd_in[50]
  PIN rw0_wd_in[51]
    DIRECTION INPUT ;
    USE SIGNAL ;
    SHAPE ABUTMENT ;
    PORT
      LAYER met3 ;
      RECT 352.840 454.770 353.740 455.070 ;
    END
  END rw0_wd_in[51]
  PIN rw0_wd_in[52]
    DIRECTION INPUT ;
    USE SIGNAL ;
    SHAPE ABUTMENT ;
    PORT
      LAYER met3 ;
      RECT 352.840 463.610 353.740 463.910 ;
    END
  END rw0_wd_in[52]
  PIN rw0_wd_in[53]
    DIRECTION INPUT ;
    USE SIGNAL ;
    SHAPE ABUTMENT ;
    PORT
      LAYER met3 ;
      RECT 352.840 472.450 353.740 472.750 ;
    END
  END rw0_wd_in[53]
  PIN rw0_wd_in[54]
    DIRECTION INPUT ;
    USE SIGNAL ;
    SHAPE ABUTMENT ;
    PORT
      LAYER met3 ;
      RECT 352.840 481.290 353.740 481.590 ;
    END
  END rw0_wd_in[54]
  PIN rw0_wd_in[55]
    DIRECTION INPUT ;
    USE SIGNAL ;
    SHAPE ABUTMENT ;
    PORT
      LAYER met3 ;
      RECT 352.840 490.130 353.740 490.430 ;
    END
  END rw0_wd_in[55]
  PIN rw0_wd_in[56]
    DIRECTION INPUT ;
    USE SIGNAL ;
    SHAPE ABUTMENT ;
    PORT
      LAYER met3 ;
      RECT 352.840 498.970 353.740 499.270 ;
    END
  END rw0_wd_in[56]
  PIN rw0_wd_in[57]
    DIRECTION INPUT ;
    USE SIGNAL ;
    SHAPE ABUTMENT ;
    PORT
      LAYER met3 ;
      RECT 352.840 507.810 353.740 508.110 ;
    END
  END rw0_wd_in[57]
  PIN rw0_wd_in[58]
    DIRECTION INPUT ;
    USE SIGNAL ;
    SHAPE ABUTMENT ;
    PORT
      LAYER met3 ;
      RECT 352.840 516.650 353.740 516.950 ;
    END
  END rw0_wd_in[58]
  PIN rw0_wd_in[59]
    DIRECTION INPUT ;
    USE SIGNAL ;
    SHAPE ABUTMENT ;
    PORT
      LAYER met3 ;
      RECT 352.840 525.490 353.740 525.790 ;
    END
  END rw0_wd_in[59]
  PIN rw0_wd_in[60]
    DIRECTION INPUT ;
    USE SIGNAL ;
    SHAPE ABUTMENT ;
    PORT
      LAYER met3 ;
      RECT 352.840 534.330 353.740 534.630 ;
    END
  END rw0_wd_in[60]
  PIN rw0_wd_in[61]
    DIRECTION INPUT ;
    USE SIGNAL ;
    SHAPE ABUTMENT ;
    PORT
      LAYER met3 ;
      RECT 352.840 543.170 353.740 543.470 ;
    END
  END rw0_wd_in[61]
  PIN rw0_wd_in[62]
    DIRECTION INPUT ;
    USE SIGNAL ;
    SHAPE ABUTMENT ;
    PORT
      LAYER met3 ;
      RECT 352.840 552.010 353.740 552.310 ;
    END
  END rw0_wd_in[62]
  PIN rw0_wd_in[63]
    DIRECTION INPUT ;
    USE SIGNAL ;
    SHAPE ABUTMENT ;
    PORT
      LAYER met3 ;
      RECT 352.840 560.850 353.740 561.150 ;
    END
  END rw0_wd_in[63]
  PIN rw0_wd_in[64]
    DIRECTION OUTPUT ;
    USE SIGNAL ;
    SHAPE ABUTMENT ;
    PORT
      LAYER met2 ;
      RECT 2.690 0.000 2.830 0.420 ;
    END
  END rw0_wd_in[64]
  PIN rw0_wd_in[65]
    DIRECTION OUTPUT ;
    USE SIGNAL ;
    SHAPE ABUTMENT ;
    PORT
      LAYER met2 ;
      RECT 4.990 0.000 5.130 0.420 ;
    END
  END rw0_wd_in[65]
  PIN rw0_wd_in[66]
    DIRECTION OUTPUT ;
    USE SIGNAL ;
    SHAPE ABUTMENT ;
    PORT
      LAYER met2 ;
      RECT 7.290 0.000 7.430 0.420 ;
    END
  END rw0_wd_in[66]
  PIN rw0_wd_in[67]
    DIRECTION OUTPUT ;
    USE SIGNAL ;
    SHAPE ABUTMENT ;
    PORT
      LAYER met2 ;
      RECT 9.590 0.000 9.730 0.420 ;
    END
  END rw0_wd_in[67]
  PIN rw0_wd_in[68]
    DIRECTION OUTPUT ;
    USE SIGNAL ;
    SHAPE ABUTMENT ;
    PORT
      LAYER met2 ;
      RECT 11.890 0.000 12.030 0.420 ;
    END
  END rw0_wd_in[68]
  PIN rw0_wd_in[69]
    DIRECTION OUTPUT ;
    USE SIGNAL ;
    SHAPE ABUTMENT ;
    PORT
      LAYER met2 ;
      RECT 14.190 0.000 14.330 0.420 ;
    END
  END rw0_wd_in[69]
  PIN rw0_wd_in[70]
    DIRECTION OUTPUT ;
    USE SIGNAL ;
    SHAPE ABUTMENT ;
    PORT
      LAYER met2 ;
      RECT 16.490 0.000 16.630 0.420 ;
    END
  END rw0_wd_in[70]
  PIN rw0_wd_in[71]
    DIRECTION OUTPUT ;
    USE SIGNAL ;
    SHAPE ABUTMENT ;
    PORT
      LAYER met2 ;
      RECT 18.790 0.000 18.930 0.420 ;
    END
  END rw0_wd_in[71]
  PIN rw0_wd_in[72]
    DIRECTION OUTPUT ;
    USE SIGNAL ;
    SHAPE ABUTMENT ;
    PORT
      LAYER met2 ;
      RECT 21.090 0.000 21.230 0.420 ;
    END
  END rw0_wd_in[72]
  PIN rw0_wd_in[73]
    DIRECTION OUTPUT ;
    USE SIGNAL ;
    SHAPE ABUTMENT ;
    PORT
      LAYER met2 ;
      RECT 23.390 0.000 23.530 0.420 ;
    END
  END rw0_wd_in[73]
  PIN rw0_wd_in[74]
    DIRECTION OUTPUT ;
    USE SIGNAL ;
    SHAPE ABUTMENT ;
    PORT
      LAYER met2 ;
      RECT 25.690 0.000 25.830 0.420 ;
    END
  END rw0_wd_in[74]
  PIN rw0_wd_in[75]
    DIRECTION OUTPUT ;
    USE SIGNAL ;
    SHAPE ABUTMENT ;
    PORT
      LAYER met2 ;
      RECT 27.990 0.000 28.130 0.420 ;
    END
  END rw0_wd_in[75]
  PIN rw0_wd_in[76]
    DIRECTION OUTPUT ;
    USE SIGNAL ;
    SHAPE ABUTMENT ;
    PORT
      LAYER met2 ;
      RECT 30.290 0.000 30.430 0.420 ;
    END
  END rw0_wd_in[76]
  PIN rw0_wd_in[77]
    DIRECTION OUTPUT ;
    USE SIGNAL ;
    SHAPE ABUTMENT ;
    PORT
      LAYER met2 ;
      RECT 32.590 0.000 32.730 0.420 ;
    END
  END rw0_wd_in[77]
  PIN rw0_wd_in[78]
    DIRECTION OUTPUT ;
    USE SIGNAL ;
    SHAPE ABUTMENT ;
    PORT
      LAYER met2 ;
      RECT 34.890 0.000 35.030 0.420 ;
    END
  END rw0_wd_in[78]
  PIN rw0_wd_in[79]
    DIRECTION OUTPUT ;
    USE SIGNAL ;
    SHAPE ABUTMENT ;
    PORT
      LAYER met2 ;
      RECT 37.190 0.000 37.330 0.420 ;
    END
  END rw0_wd_in[79]
  PIN rw0_wd_in[80]
    DIRECTION OUTPUT ;
    USE SIGNAL ;
    SHAPE ABUTMENT ;
    PORT
      LAYER met2 ;
      RECT 39.490 0.000 39.630 0.420 ;
    END
  END rw0_wd_in[80]
  PIN rw0_wd_in[81]
    DIRECTION OUTPUT ;
    USE SIGNAL ;
    SHAPE ABUTMENT ;
    PORT
      LAYER met2 ;
      RECT 41.790 0.000 41.930 0.420 ;
    END
  END rw0_wd_in[81]
  PIN rw0_wd_in[82]
    DIRECTION OUTPUT ;
    USE SIGNAL ;
    SHAPE ABUTMENT ;
    PORT
      LAYER met2 ;
      RECT 44.090 0.000 44.230 0.420 ;
    END
  END rw0_wd_in[82]
  PIN rw0_wd_in[83]
    DIRECTION OUTPUT ;
    USE SIGNAL ;
    SHAPE ABUTMENT ;
    PORT
      LAYER met2 ;
      RECT 46.390 0.000 46.530 0.420 ;
    END
  END rw0_wd_in[83]
  PIN rw0_wd_in[84]
    DIRECTION OUTPUT ;
    USE SIGNAL ;
    SHAPE ABUTMENT ;
    PORT
      LAYER met2 ;
      RECT 48.690 0.000 48.830 0.420 ;
    END
  END rw0_wd_in[84]
  PIN rw0_wd_in[85]
    DIRECTION OUTPUT ;
    USE SIGNAL ;
    SHAPE ABUTMENT ;
    PORT
      LAYER met2 ;
      RECT 50.990 0.000 51.130 0.420 ;
    END
  END rw0_wd_in[85]
  PIN rw0_wd_in[86]
    DIRECTION OUTPUT ;
    USE SIGNAL ;
    SHAPE ABUTMENT ;
    PORT
      LAYER met2 ;
      RECT 53.290 0.000 53.430 0.420 ;
    END
  END rw0_wd_in[86]
  PIN rw0_wd_in[87]
    DIRECTION OUTPUT ;
    USE SIGNAL ;
    SHAPE ABUTMENT ;
    PORT
      LAYER met2 ;
      RECT 55.590 0.000 55.730 0.420 ;
    END
  END rw0_wd_in[87]
  PIN rw0_wd_in[88]
    DIRECTION OUTPUT ;
    USE SIGNAL ;
    SHAPE ABUTMENT ;
    PORT
      LAYER met2 ;
      RECT 57.890 0.000 58.030 0.420 ;
    END
  END rw0_wd_in[88]
  PIN rw0_wd_in[89]
    DIRECTION OUTPUT ;
    USE SIGNAL ;
    SHAPE ABUTMENT ;
    PORT
      LAYER met2 ;
      RECT 60.190 0.000 60.330 0.420 ;
    END
  END rw0_wd_in[89]
  PIN rw0_wd_in[90]
    DIRECTION OUTPUT ;
    USE SIGNAL ;
    SHAPE ABUTMENT ;
    PORT
      LAYER met2 ;
      RECT 62.490 0.000 62.630 0.420 ;
    END
  END rw0_wd_in[90]
  PIN rw0_wd_in[91]
    DIRECTION OUTPUT ;
    USE SIGNAL ;
    SHAPE ABUTMENT ;
    PORT
      LAYER met2 ;
      RECT 64.790 0.000 64.930 0.420 ;
    END
  END rw0_wd_in[91]
  PIN rw0_wd_in[92]
    DIRECTION OUTPUT ;
    USE SIGNAL ;
    SHAPE ABUTMENT ;
    PORT
      LAYER met2 ;
      RECT 67.090 0.000 67.230 0.420 ;
    END
  END rw0_wd_in[92]
  PIN rw0_wd_in[93]
    DIRECTION OUTPUT ;
    USE SIGNAL ;
    SHAPE ABUTMENT ;
    PORT
      LAYER met2 ;
      RECT 69.390 0.000 69.530 0.420 ;
    END
  END rw0_wd_in[93]
  PIN rw0_wd_in[94]
    DIRECTION OUTPUT ;
    USE SIGNAL ;
    SHAPE ABUTMENT ;
    PORT
      LAYER met2 ;
      RECT 71.690 0.000 71.830 0.420 ;
    END
  END rw0_wd_in[94]
  PIN rw0_wd_in[95]
    DIRECTION OUTPUT ;
    USE SIGNAL ;
    SHAPE ABUTMENT ;
    PORT
      LAYER met2 ;
      RECT 73.990 0.000 74.130 0.420 ;
    END
  END rw0_wd_in[95]
  PIN rw0_wd_in[96]
    DIRECTION OUTPUT ;
    USE SIGNAL ;
    SHAPE ABUTMENT ;
    PORT
      LAYER met2 ;
      RECT 76.290 0.000 76.430 0.420 ;
    END
  END rw0_wd_in[96]
  PIN rw0_wd_in[97]
    DIRECTION OUTPUT ;
    USE SIGNAL ;
    SHAPE ABUTMENT ;
    PORT
      LAYER met2 ;
      RECT 78.590 0.000 78.730 0.420 ;
    END
  END rw0_wd_in[97]
  PIN rw0_wd_in[98]
    DIRECTION OUTPUT ;
    USE SIGNAL ;
    SHAPE ABUTMENT ;
    PORT
      LAYER met2 ;
      RECT 80.890 0.000 81.030 0.420 ;
    END
  END rw0_wd_in[98]
  PIN rw0_wd_in[99]
    DIRECTION OUTPUT ;
    USE SIGNAL ;
    SHAPE ABUTMENT ;
    PORT
      LAYER met2 ;
      RECT 83.190 0.000 83.330 0.420 ;
    END
  END rw0_wd_in[99]
  PIN rw0_wd_in[100]
    DIRECTION OUTPUT ;
    USE SIGNAL ;
    SHAPE ABUTMENT ;
    PORT
      LAYER met2 ;
      RECT 85.490 0.000 85.630 0.420 ;
    END
  END rw0_wd_in[100]
  PIN rw0_wd_in[101]
    DIRECTION OUTPUT ;
    USE SIGNAL ;
    SHAPE ABUTMENT ;
    PORT
      LAYER met2 ;
      RECT 87.790 0.000 87.930 0.420 ;
    END
  END rw0_wd_in[101]
  PIN rw0_wd_in[102]
    DIRECTION OUTPUT ;
    USE SIGNAL ;
    SHAPE ABUTMENT ;
    PORT
      LAYER met2 ;
      RECT 90.090 0.000 90.230 0.420 ;
    END
  END rw0_wd_in[102]
  PIN rw0_wd_in[103]
    DIRECTION OUTPUT ;
    USE SIGNAL ;
    SHAPE ABUTMENT ;
    PORT
      LAYER met2 ;
      RECT 92.390 0.000 92.530 0.420 ;
    END
  END rw0_wd_in[103]
  PIN rw0_wd_in[104]
    DIRECTION OUTPUT ;
    USE SIGNAL ;
    SHAPE ABUTMENT ;
    PORT
      LAYER met2 ;
      RECT 94.690 0.000 94.830 0.420 ;
    END
  END rw0_wd_in[104]
  PIN rw0_wd_in[105]
    DIRECTION OUTPUT ;
    USE SIGNAL ;
    SHAPE ABUTMENT ;
    PORT
      LAYER met2 ;
      RECT 96.990 0.000 97.130 0.420 ;
    END
  END rw0_wd_in[105]
  PIN rw0_wd_in[106]
    DIRECTION OUTPUT ;
    USE SIGNAL ;
    SHAPE ABUTMENT ;
    PORT
      LAYER met2 ;
      RECT 99.290 0.000 99.430 0.420 ;
    END
  END rw0_wd_in[106]
  PIN rw0_wd_in[107]
    DIRECTION OUTPUT ;
    USE SIGNAL ;
    SHAPE ABUTMENT ;
    PORT
      LAYER met2 ;
      RECT 101.590 0.000 101.730 0.420 ;
    END
  END rw0_wd_in[107]
  PIN rw0_wd_in[108]
    DIRECTION OUTPUT ;
    USE SIGNAL ;
    SHAPE ABUTMENT ;
    PORT
      LAYER met2 ;
      RECT 103.890 0.000 104.030 0.420 ;
    END
  END rw0_wd_in[108]
  PIN rw0_wd_in[109]
    DIRECTION OUTPUT ;
    USE SIGNAL ;
    SHAPE ABUTMENT ;
    PORT
      LAYER met2 ;
      RECT 106.190 0.000 106.330 0.420 ;
    END
  END rw0_wd_in[109]
  PIN rw0_wd_in[110]
    DIRECTION OUTPUT ;
    USE SIGNAL ;
    SHAPE ABUTMENT ;
    PORT
      LAYER met2 ;
      RECT 108.490 0.000 108.630 0.420 ;
    END
  END rw0_wd_in[110]
  PIN rw0_wd_in[111]
    DIRECTION OUTPUT ;
    USE SIGNAL ;
    SHAPE ABUTMENT ;
    PORT
      LAYER met2 ;
      RECT 110.790 0.000 110.930 0.420 ;
    END
  END rw0_wd_in[111]
  PIN rw0_wd_in[112]
    DIRECTION OUTPUT ;
    USE SIGNAL ;
    SHAPE ABUTMENT ;
    PORT
      LAYER met2 ;
      RECT 113.090 0.000 113.230 0.420 ;
    END
  END rw0_wd_in[112]
  PIN rw0_wd_in[113]
    DIRECTION OUTPUT ;
    USE SIGNAL ;
    SHAPE ABUTMENT ;
    PORT
      LAYER met2 ;
      RECT 115.390 0.000 115.530 0.420 ;
    END
  END rw0_wd_in[113]
  PIN rw0_wd_in[114]
    DIRECTION OUTPUT ;
    USE SIGNAL ;
    SHAPE ABUTMENT ;
    PORT
      LAYER met2 ;
      RECT 117.690 0.000 117.830 0.420 ;
    END
  END rw0_wd_in[114]
  PIN rw0_wd_in[115]
    DIRECTION OUTPUT ;
    USE SIGNAL ;
    SHAPE ABUTMENT ;
    PORT
      LAYER met2 ;
      RECT 119.990 0.000 120.130 0.420 ;
    END
  END rw0_wd_in[115]
  PIN rw0_wd_in[116]
    DIRECTION OUTPUT ;
    USE SIGNAL ;
    SHAPE ABUTMENT ;
    PORT
      LAYER met2 ;
      RECT 122.290 0.000 122.430 0.420 ;
    END
  END rw0_wd_in[116]
  PIN rw0_wd_in[117]
    DIRECTION OUTPUT ;
    USE SIGNAL ;
    SHAPE ABUTMENT ;
    PORT
      LAYER met2 ;
      RECT 124.590 0.000 124.730 0.420 ;
    END
  END rw0_wd_in[117]
  PIN rw0_wd_in[118]
    DIRECTION OUTPUT ;
    USE SIGNAL ;
    SHAPE ABUTMENT ;
    PORT
      LAYER met2 ;
      RECT 126.890 0.000 127.030 0.420 ;
    END
  END rw0_wd_in[118]
  PIN rw0_wd_in[119]
    DIRECTION OUTPUT ;
    USE SIGNAL ;
    SHAPE ABUTMENT ;
    PORT
      LAYER met2 ;
      RECT 129.190 0.000 129.330 0.420 ;
    END
  END rw0_wd_in[119]
  PIN rw0_wd_in[120]
    DIRECTION OUTPUT ;
    USE SIGNAL ;
    SHAPE ABUTMENT ;
    PORT
      LAYER met2 ;
      RECT 131.490 0.000 131.630 0.420 ;
    END
  END rw0_wd_in[120]
  PIN rw0_wd_in[121]
    DIRECTION OUTPUT ;
    USE SIGNAL ;
    SHAPE ABUTMENT ;
    PORT
      LAYER met2 ;
      RECT 133.790 0.000 133.930 0.420 ;
    END
  END rw0_wd_in[121]
  PIN rw0_wd_in[122]
    DIRECTION OUTPUT ;
    USE SIGNAL ;
    SHAPE ABUTMENT ;
    PORT
      LAYER met2 ;
      RECT 136.090 0.000 136.230 0.420 ;
    END
  END rw0_wd_in[122]
  PIN rw0_wd_in[123]
    DIRECTION OUTPUT ;
    USE SIGNAL ;
    SHAPE ABUTMENT ;
    PORT
      LAYER met2 ;
      RECT 138.390 0.000 138.530 0.420 ;
    END
  END rw0_wd_in[123]
  PIN rw0_wd_in[124]
    DIRECTION OUTPUT ;
    USE SIGNAL ;
    SHAPE ABUTMENT ;
    PORT
      LAYER met2 ;
      RECT 140.690 0.000 140.830 0.420 ;
    END
  END rw0_wd_in[124]
  PIN rw0_wd_in[125]
    DIRECTION OUTPUT ;
    USE SIGNAL ;
    SHAPE ABUTMENT ;
    PORT
      LAYER met2 ;
      RECT 142.990 0.000 143.130 0.420 ;
    END
  END rw0_wd_in[125]
  PIN rw0_wd_in[126]
    DIRECTION OUTPUT ;
    USE SIGNAL ;
    SHAPE ABUTMENT ;
    PORT
      LAYER met2 ;
      RECT 145.290 0.000 145.430 0.420 ;
    END
  END rw0_wd_in[126]
  PIN rw0_wd_in[127]
    DIRECTION OUTPUT ;
    USE SIGNAL ;
    SHAPE ABUTMENT ;
    PORT
      LAYER met2 ;
      RECT 147.590 0.000 147.730 0.420 ;
    END
  END rw0_wd_in[127]
  PIN rw0_rd_out[0]
    DIRECTION OUTPUT ;
    USE SIGNAL ;
    SHAPE ABUTMENT ;
    PORT
      LAYER met2 ;
      RECT 149.890 0.000 150.030 0.420 ;
    END
  END rw0_rd_out[0]
  PIN rw0_rd_out[1]
    DIRECTION OUTPUT ;
    USE SIGNAL ;
    SHAPE ABUTMENT ;
    PORT
      LAYER met2 ;
      RECT 152.190 0.000 152.330 0.420 ;
    END
  END rw0_rd_out[1]
  PIN rw0_rd_out[2]
    DIRECTION OUTPUT ;
    USE SIGNAL ;
    SHAPE ABUTMENT ;
    PORT
      LAYER met2 ;
      RECT 154.490 0.000 154.630 0.420 ;
    END
  END rw0_rd_out[2]
  PIN rw0_rd_out[3]
    DIRECTION OUTPUT ;
    USE SIGNAL ;
    SHAPE ABUTMENT ;
    PORT
      LAYER met2 ;
      RECT 156.790 0.000 156.930 0.420 ;
    END
  END rw0_rd_out[3]
  PIN rw0_rd_out[4]
    DIRECTION OUTPUT ;
    USE SIGNAL ;
    SHAPE ABUTMENT ;
    PORT
      LAYER met2 ;
      RECT 159.090 0.000 159.230 0.420 ;
    END
  END rw0_rd_out[4]
  PIN rw0_rd_out[5]
    DIRECTION OUTPUT ;
    USE SIGNAL ;
    SHAPE ABUTMENT ;
    PORT
      LAYER met2 ;
      RECT 161.390 0.000 161.530 0.420 ;
    END
  END rw0_rd_out[5]
  PIN rw0_rd_out[6]
    DIRECTION OUTPUT ;
    USE SIGNAL ;
    SHAPE ABUTMENT ;
    PORT
      LAYER met2 ;
      RECT 163.690 0.000 163.830 0.420 ;
    END
  END rw0_rd_out[6]
  PIN rw0_rd_out[7]
    DIRECTION OUTPUT ;
    USE SIGNAL ;
    SHAPE ABUTMENT ;
    PORT
      LAYER met2 ;
      RECT 165.990 0.000 166.130 0.420 ;
    END
  END rw0_rd_out[7]
  PIN rw0_rd_out[8]
    DIRECTION OUTPUT ;
    USE SIGNAL ;
    SHAPE ABUTMENT ;
    PORT
      LAYER met2 ;
      RECT 168.290 0.000 168.430 0.420 ;
    END
  END rw0_rd_out[8]
  PIN rw0_rd_out[9]
    DIRECTION OUTPUT ;
    USE SIGNAL ;
    SHAPE ABUTMENT ;
    PORT
      LAYER met2 ;
      RECT 170.590 0.000 170.730 0.420 ;
    END
  END rw0_rd_out[9]
  PIN rw0_rd_out[10]
    DIRECTION OUTPUT ;
    USE SIGNAL ;
    SHAPE ABUTMENT ;
    PORT
      LAYER met2 ;
      RECT 172.890 0.000 173.030 0.420 ;
    END
  END rw0_rd_out[10]
  PIN rw0_rd_out[11]
    DIRECTION OUTPUT ;
    USE SIGNAL ;
    SHAPE ABUTMENT ;
    PORT
      LAYER met2 ;
      RECT 175.190 0.000 175.330 0.420 ;
    END
  END rw0_rd_out[11]
  PIN rw0_rd_out[12]
    DIRECTION OUTPUT ;
    USE SIGNAL ;
    SHAPE ABUTMENT ;
    PORT
      LAYER met2 ;
      RECT 177.490 0.000 177.630 0.420 ;
    END
  END rw0_rd_out[12]
  PIN rw0_rd_out[13]
    DIRECTION OUTPUT ;
    USE SIGNAL ;
    SHAPE ABUTMENT ;
    PORT
      LAYER met2 ;
      RECT 179.790 0.000 179.930 0.420 ;
    END
  END rw0_rd_out[13]
  PIN rw0_rd_out[14]
    DIRECTION OUTPUT ;
    USE SIGNAL ;
    SHAPE ABUTMENT ;
    PORT
      LAYER met2 ;
      RECT 182.090 0.000 182.230 0.420 ;
    END
  END rw0_rd_out[14]
  PIN rw0_rd_out[15]
    DIRECTION OUTPUT ;
    USE SIGNAL ;
    SHAPE ABUTMENT ;
    PORT
      LAYER met2 ;
      RECT 184.390 0.000 184.530 0.420 ;
    END
  END rw0_rd_out[15]
  PIN rw0_rd_out[16]
    DIRECTION OUTPUT ;
    USE SIGNAL ;
    SHAPE ABUTMENT ;
    PORT
      LAYER met2 ;
      RECT 186.690 0.000 186.830 0.420 ;
    END
  END rw0_rd_out[16]
  PIN rw0_rd_out[17]
    DIRECTION OUTPUT ;
    USE SIGNAL ;
    SHAPE ABUTMENT ;
    PORT
      LAYER met2 ;
      RECT 188.990 0.000 189.130 0.420 ;
    END
  END rw0_rd_out[17]
  PIN rw0_rd_out[18]
    DIRECTION OUTPUT ;
    USE SIGNAL ;
    SHAPE ABUTMENT ;
    PORT
      LAYER met2 ;
      RECT 191.290 0.000 191.430 0.420 ;
    END
  END rw0_rd_out[18]
  PIN rw0_rd_out[19]
    DIRECTION OUTPUT ;
    USE SIGNAL ;
    SHAPE ABUTMENT ;
    PORT
      LAYER met2 ;
      RECT 193.590 0.000 193.730 0.420 ;
    END
  END rw0_rd_out[19]
  PIN rw0_rd_out[20]
    DIRECTION OUTPUT ;
    USE SIGNAL ;
    SHAPE ABUTMENT ;
    PORT
      LAYER met2 ;
      RECT 195.890 0.000 196.030 0.420 ;
    END
  END rw0_rd_out[20]
  PIN rw0_rd_out[21]
    DIRECTION OUTPUT ;
    USE SIGNAL ;
    SHAPE ABUTMENT ;
    PORT
      LAYER met2 ;
      RECT 198.190 0.000 198.330 0.420 ;
    END
  END rw0_rd_out[21]
  PIN rw0_rd_out[22]
    DIRECTION OUTPUT ;
    USE SIGNAL ;
    SHAPE ABUTMENT ;
    PORT
      LAYER met2 ;
      RECT 200.490 0.000 200.630 0.420 ;
    END
  END rw0_rd_out[22]
  PIN rw0_rd_out[23]
    DIRECTION OUTPUT ;
    USE SIGNAL ;
    SHAPE ABUTMENT ;
    PORT
      LAYER met2 ;
      RECT 202.790 0.000 202.930 0.420 ;
    END
  END rw0_rd_out[23]
  PIN rw0_rd_out[24]
    DIRECTION OUTPUT ;
    USE SIGNAL ;
    SHAPE ABUTMENT ;
    PORT
      LAYER met2 ;
      RECT 205.090 0.000 205.230 0.420 ;
    END
  END rw0_rd_out[24]
  PIN rw0_rd_out[25]
    DIRECTION OUTPUT ;
    USE SIGNAL ;
    SHAPE ABUTMENT ;
    PORT
      LAYER met2 ;
      RECT 207.390 0.000 207.530 0.420 ;
    END
  END rw0_rd_out[25]
  PIN rw0_rd_out[26]
    DIRECTION OUTPUT ;
    USE SIGNAL ;
    SHAPE ABUTMENT ;
    PORT
      LAYER met2 ;
      RECT 209.690 0.000 209.830 0.420 ;
    END
  END rw0_rd_out[26]
  PIN rw0_rd_out[27]
    DIRECTION OUTPUT ;
    USE SIGNAL ;
    SHAPE ABUTMENT ;
    PORT
      LAYER met2 ;
      RECT 211.990 0.000 212.130 0.420 ;
    END
  END rw0_rd_out[27]
  PIN rw0_rd_out[28]
    DIRECTION OUTPUT ;
    USE SIGNAL ;
    SHAPE ABUTMENT ;
    PORT
      LAYER met2 ;
      RECT 214.290 0.000 214.430 0.420 ;
    END
  END rw0_rd_out[28]
  PIN rw0_rd_out[29]
    DIRECTION OUTPUT ;
    USE SIGNAL ;
    SHAPE ABUTMENT ;
    PORT
      LAYER met2 ;
      RECT 216.590 0.000 216.730 0.420 ;
    END
  END rw0_rd_out[29]
  PIN rw0_rd_out[30]
    DIRECTION OUTPUT ;
    USE SIGNAL ;
    SHAPE ABUTMENT ;
    PORT
      LAYER met2 ;
      RECT 218.890 0.000 219.030 0.420 ;
    END
  END rw0_rd_out[30]
  PIN rw0_rd_out[31]
    DIRECTION OUTPUT ;
    USE SIGNAL ;
    SHAPE ABUTMENT ;
    PORT
      LAYER met2 ;
      RECT 221.190 0.000 221.330 0.420 ;
    END
  END rw0_rd_out[31]
  PIN rw0_rd_out[32]
    DIRECTION OUTPUT ;
    USE SIGNAL ;
    SHAPE ABUTMENT ;
    PORT
      LAYER met2 ;
      RECT 223.490 0.000 223.630 0.420 ;
    END
  END rw0_rd_out[32]
  PIN rw0_rd_out[33]
    DIRECTION OUTPUT ;
    USE SIGNAL ;
    SHAPE ABUTMENT ;
    PORT
      LAYER met2 ;
      RECT 225.790 0.000 225.930 0.420 ;
    END
  END rw0_rd_out[33]
  PIN rw0_rd_out[34]
    DIRECTION OUTPUT ;
    USE SIGNAL ;
    SHAPE ABUTMENT ;
    PORT
      LAYER met2 ;
      RECT 228.090 0.000 228.230 0.420 ;
    END
  END rw0_rd_out[34]
  PIN rw0_rd_out[35]
    DIRECTION OUTPUT ;
    USE SIGNAL ;
    SHAPE ABUTMENT ;
    PORT
      LAYER met2 ;
      RECT 230.390 0.000 230.530 0.420 ;
    END
  END rw0_rd_out[35]
  PIN rw0_rd_out[36]
    DIRECTION OUTPUT ;
    USE SIGNAL ;
    SHAPE ABUTMENT ;
    PORT
      LAYER met2 ;
      RECT 232.690 0.000 232.830 0.420 ;
    END
  END rw0_rd_out[36]
  PIN rw0_rd_out[37]
    DIRECTION OUTPUT ;
    USE SIGNAL ;
    SHAPE ABUTMENT ;
    PORT
      LAYER met2 ;
      RECT 234.990 0.000 235.130 0.420 ;
    END
  END rw0_rd_out[37]
  PIN rw0_rd_out[38]
    DIRECTION OUTPUT ;
    USE SIGNAL ;
    SHAPE ABUTMENT ;
    PORT
      LAYER met2 ;
      RECT 237.290 0.000 237.430 0.420 ;
    END
  END rw0_rd_out[38]
  PIN rw0_rd_out[39]
    DIRECTION OUTPUT ;
    USE SIGNAL ;
    SHAPE ABUTMENT ;
    PORT
      LAYER met2 ;
      RECT 239.590 0.000 239.730 0.420 ;
    END
  END rw0_rd_out[39]
  PIN rw0_rd_out[40]
    DIRECTION OUTPUT ;
    USE SIGNAL ;
    SHAPE ABUTMENT ;
    PORT
      LAYER met2 ;
      RECT 241.890 0.000 242.030 0.420 ;
    END
  END rw0_rd_out[40]
  PIN rw0_rd_out[41]
    DIRECTION OUTPUT ;
    USE SIGNAL ;
    SHAPE ABUTMENT ;
    PORT
      LAYER met2 ;
      RECT 244.190 0.000 244.330 0.420 ;
    END
  END rw0_rd_out[41]
  PIN rw0_rd_out[42]
    DIRECTION OUTPUT ;
    USE SIGNAL ;
    SHAPE ABUTMENT ;
    PORT
      LAYER met2 ;
      RECT 246.490 0.000 246.630 0.420 ;
    END
  END rw0_rd_out[42]
  PIN rw0_rd_out[43]
    DIRECTION OUTPUT ;
    USE SIGNAL ;
    SHAPE ABUTMENT ;
    PORT
      LAYER met2 ;
      RECT 248.790 0.000 248.930 0.420 ;
    END
  END rw0_rd_out[43]
  PIN rw0_rd_out[44]
    DIRECTION OUTPUT ;
    USE SIGNAL ;
    SHAPE ABUTMENT ;
    PORT
      LAYER met2 ;
      RECT 251.090 0.000 251.230 0.420 ;
    END
  END rw0_rd_out[44]
  PIN rw0_rd_out[45]
    DIRECTION OUTPUT ;
    USE SIGNAL ;
    SHAPE ABUTMENT ;
    PORT
      LAYER met2 ;
      RECT 253.390 0.000 253.530 0.420 ;
    END
  END rw0_rd_out[45]
  PIN rw0_rd_out[46]
    DIRECTION OUTPUT ;
    USE SIGNAL ;
    SHAPE ABUTMENT ;
    PORT
      LAYER met2 ;
      RECT 255.690 0.000 255.830 0.420 ;
    END
  END rw0_rd_out[46]
  PIN rw0_rd_out[47]
    DIRECTION OUTPUT ;
    USE SIGNAL ;
    SHAPE ABUTMENT ;
    PORT
      LAYER met2 ;
      RECT 257.990 0.000 258.130 0.420 ;
    END
  END rw0_rd_out[47]
  PIN rw0_rd_out[48]
    DIRECTION OUTPUT ;
    USE SIGNAL ;
    SHAPE ABUTMENT ;
    PORT
      LAYER met2 ;
      RECT 260.290 0.000 260.430 0.420 ;
    END
  END rw0_rd_out[48]
  PIN rw0_rd_out[49]
    DIRECTION OUTPUT ;
    USE SIGNAL ;
    SHAPE ABUTMENT ;
    PORT
      LAYER met2 ;
      RECT 262.590 0.000 262.730 0.420 ;
    END
  END rw0_rd_out[49]
  PIN rw0_rd_out[50]
    DIRECTION OUTPUT ;
    USE SIGNAL ;
    SHAPE ABUTMENT ;
    PORT
      LAYER met2 ;
      RECT 264.890 0.000 265.030 0.420 ;
    END
  END rw0_rd_out[50]
  PIN rw0_rd_out[51]
    DIRECTION OUTPUT ;
    USE SIGNAL ;
    SHAPE ABUTMENT ;
    PORT
      LAYER met2 ;
      RECT 267.190 0.000 267.330 0.420 ;
    END
  END rw0_rd_out[51]
  PIN rw0_rd_out[52]
    DIRECTION OUTPUT ;
    USE SIGNAL ;
    SHAPE ABUTMENT ;
    PORT
      LAYER met2 ;
      RECT 269.490 0.000 269.630 0.420 ;
    END
  END rw0_rd_out[52]
  PIN rw0_rd_out[53]
    DIRECTION OUTPUT ;
    USE SIGNAL ;
    SHAPE ABUTMENT ;
    PORT
      LAYER met2 ;
      RECT 271.790 0.000 271.930 0.420 ;
    END
  END rw0_rd_out[53]
  PIN rw0_rd_out[54]
    DIRECTION OUTPUT ;
    USE SIGNAL ;
    SHAPE ABUTMENT ;
    PORT
      LAYER met2 ;
      RECT 274.090 0.000 274.230 0.420 ;
    END
  END rw0_rd_out[54]
  PIN rw0_rd_out[55]
    DIRECTION OUTPUT ;
    USE SIGNAL ;
    SHAPE ABUTMENT ;
    PORT
      LAYER met2 ;
      RECT 276.390 0.000 276.530 0.420 ;
    END
  END rw0_rd_out[55]
  PIN rw0_rd_out[56]
    DIRECTION OUTPUT ;
    USE SIGNAL ;
    SHAPE ABUTMENT ;
    PORT
      LAYER met2 ;
      RECT 278.690 0.000 278.830 0.420 ;
    END
  END rw0_rd_out[56]
  PIN rw0_rd_out[57]
    DIRECTION OUTPUT ;
    USE SIGNAL ;
    SHAPE ABUTMENT ;
    PORT
      LAYER met2 ;
      RECT 280.990 0.000 281.130 0.420 ;
    END
  END rw0_rd_out[57]
  PIN rw0_rd_out[58]
    DIRECTION OUTPUT ;
    USE SIGNAL ;
    SHAPE ABUTMENT ;
    PORT
      LAYER met2 ;
      RECT 283.290 0.000 283.430 0.420 ;
    END
  END rw0_rd_out[58]
  PIN rw0_rd_out[59]
    DIRECTION OUTPUT ;
    USE SIGNAL ;
    SHAPE ABUTMENT ;
    PORT
      LAYER met2 ;
      RECT 285.590 0.000 285.730 0.420 ;
    END
  END rw0_rd_out[59]
  PIN rw0_rd_out[60]
    DIRECTION OUTPUT ;
    USE SIGNAL ;
    SHAPE ABUTMENT ;
    PORT
      LAYER met2 ;
      RECT 287.890 0.000 288.030 0.420 ;
    END
  END rw0_rd_out[60]
  PIN rw0_rd_out[61]
    DIRECTION OUTPUT ;
    USE SIGNAL ;
    SHAPE ABUTMENT ;
    PORT
      LAYER met2 ;
      RECT 290.190 0.000 290.330 0.420 ;
    END
  END rw0_rd_out[61]
  PIN rw0_rd_out[62]
    DIRECTION OUTPUT ;
    USE SIGNAL ;
    SHAPE ABUTMENT ;
    PORT
      LAYER met2 ;
      RECT 292.490 0.000 292.630 0.420 ;
    END
  END rw0_rd_out[62]
  PIN rw0_rd_out[63]
    DIRECTION OUTPUT ;
    USE SIGNAL ;
    SHAPE ABUTMENT ;
    PORT
      LAYER met2 ;
      RECT 294.790 0.000 294.930 0.420 ;
    END
  END rw0_rd_out[63]
  PIN rw0_rd_out[64]
    DIRECTION OUTPUT ;
    USE SIGNAL ;
    SHAPE ABUTMENT ;
    PORT
      LAYER met2 ;
      RECT 149.890 655.100 150.030 655.520 ;
    END
  END rw0_rd_out[64]
  PIN rw0_rd_out[65]
    DIRECTION OUTPUT ;
    USE SIGNAL ;
    SHAPE ABUTMENT ;
    PORT
      LAYER met2 ;
      RECT 152.190 655.100 152.330 655.520 ;
    END
  END rw0_rd_out[65]
  PIN rw0_rd_out[66]
    DIRECTION OUTPUT ;
    USE SIGNAL ;
    SHAPE ABUTMENT ;
    PORT
      LAYER met2 ;
      RECT 154.490 655.100 154.630 655.520 ;
    END
  END rw0_rd_out[66]
  PIN rw0_rd_out[67]
    DIRECTION OUTPUT ;
    USE SIGNAL ;
    SHAPE ABUTMENT ;
    PORT
      LAYER met2 ;
      RECT 156.790 655.100 156.930 655.520 ;
    END
  END rw0_rd_out[67]
  PIN rw0_rd_out[68]
    DIRECTION OUTPUT ;
    USE SIGNAL ;
    SHAPE ABUTMENT ;
    PORT
      LAYER met2 ;
      RECT 159.090 655.100 159.230 655.520 ;
    END
  END rw0_rd_out[68]
  PIN rw0_rd_out[69]
    DIRECTION OUTPUT ;
    USE SIGNAL ;
    SHAPE ABUTMENT ;
    PORT
      LAYER met2 ;
      RECT 161.390 655.100 161.530 655.520 ;
    END
  END rw0_rd_out[69]
  PIN rw0_rd_out[70]
    DIRECTION OUTPUT ;
    USE SIGNAL ;
    SHAPE ABUTMENT ;
    PORT
      LAYER met2 ;
      RECT 163.690 655.100 163.830 655.520 ;
    END
  END rw0_rd_out[70]
  PIN rw0_rd_out[71]
    DIRECTION OUTPUT ;
    USE SIGNAL ;
    SHAPE ABUTMENT ;
    PORT
      LAYER met2 ;
      RECT 165.990 655.100 166.130 655.520 ;
    END
  END rw0_rd_out[71]
  PIN rw0_rd_out[72]
    DIRECTION OUTPUT ;
    USE SIGNAL ;
    SHAPE ABUTMENT ;
    PORT
      LAYER met2 ;
      RECT 168.290 655.100 168.430 655.520 ;
    END
  END rw0_rd_out[72]
  PIN rw0_rd_out[73]
    DIRECTION OUTPUT ;
    USE SIGNAL ;
    SHAPE ABUTMENT ;
    PORT
      LAYER met2 ;
      RECT 170.590 655.100 170.730 655.520 ;
    END
  END rw0_rd_out[73]
  PIN rw0_rd_out[74]
    DIRECTION OUTPUT ;
    USE SIGNAL ;
    SHAPE ABUTMENT ;
    PORT
      LAYER met2 ;
      RECT 172.890 655.100 173.030 655.520 ;
    END
  END rw0_rd_out[74]
  PIN rw0_rd_out[75]
    DIRECTION OUTPUT ;
    USE SIGNAL ;
    SHAPE ABUTMENT ;
    PORT
      LAYER met2 ;
      RECT 175.190 655.100 175.330 655.520 ;
    END
  END rw0_rd_out[75]
  PIN rw0_rd_out[76]
    DIRECTION OUTPUT ;
    USE SIGNAL ;
    SHAPE ABUTMENT ;
    PORT
      LAYER met2 ;
      RECT 177.490 655.100 177.630 655.520 ;
    END
  END rw0_rd_out[76]
  PIN rw0_rd_out[77]
    DIRECTION OUTPUT ;
    USE SIGNAL ;
    SHAPE ABUTMENT ;
    PORT
      LAYER met2 ;
      RECT 179.790 655.100 179.930 655.520 ;
    END
  END rw0_rd_out[77]
  PIN rw0_rd_out[78]
    DIRECTION OUTPUT ;
    USE SIGNAL ;
    SHAPE ABUTMENT ;
    PORT
      LAYER met2 ;
      RECT 182.090 655.100 182.230 655.520 ;
    END
  END rw0_rd_out[78]
  PIN rw0_rd_out[79]
    DIRECTION OUTPUT ;
    USE SIGNAL ;
    SHAPE ABUTMENT ;
    PORT
      LAYER met2 ;
      RECT 184.390 655.100 184.530 655.520 ;
    END
  END rw0_rd_out[79]
  PIN rw0_rd_out[80]
    DIRECTION OUTPUT ;
    USE SIGNAL ;
    SHAPE ABUTMENT ;
    PORT
      LAYER met2 ;
      RECT 186.690 655.100 186.830 655.520 ;
    END
  END rw0_rd_out[80]
  PIN rw0_rd_out[81]
    DIRECTION OUTPUT ;
    USE SIGNAL ;
    SHAPE ABUTMENT ;
    PORT
      LAYER met2 ;
      RECT 188.990 655.100 189.130 655.520 ;
    END
  END rw0_rd_out[81]
  PIN rw0_rd_out[82]
    DIRECTION OUTPUT ;
    USE SIGNAL ;
    SHAPE ABUTMENT ;
    PORT
      LAYER met2 ;
      RECT 191.290 655.100 191.430 655.520 ;
    END
  END rw0_rd_out[82]
  PIN rw0_rd_out[83]
    DIRECTION OUTPUT ;
    USE SIGNAL ;
    SHAPE ABUTMENT ;
    PORT
      LAYER met2 ;
      RECT 193.590 655.100 193.730 655.520 ;
    END
  END rw0_rd_out[83]
  PIN rw0_rd_out[84]
    DIRECTION OUTPUT ;
    USE SIGNAL ;
    SHAPE ABUTMENT ;
    PORT
      LAYER met2 ;
      RECT 195.890 655.100 196.030 655.520 ;
    END
  END rw0_rd_out[84]
  PIN rw0_rd_out[85]
    DIRECTION OUTPUT ;
    USE SIGNAL ;
    SHAPE ABUTMENT ;
    PORT
      LAYER met2 ;
      RECT 198.190 655.100 198.330 655.520 ;
    END
  END rw0_rd_out[85]
  PIN rw0_rd_out[86]
    DIRECTION OUTPUT ;
    USE SIGNAL ;
    SHAPE ABUTMENT ;
    PORT
      LAYER met2 ;
      RECT 200.490 655.100 200.630 655.520 ;
    END
  END rw0_rd_out[86]
  PIN rw0_rd_out[87]
    DIRECTION OUTPUT ;
    USE SIGNAL ;
    SHAPE ABUTMENT ;
    PORT
      LAYER met2 ;
      RECT 202.790 655.100 202.930 655.520 ;
    END
  END rw0_rd_out[87]
  PIN rw0_rd_out[88]
    DIRECTION OUTPUT ;
    USE SIGNAL ;
    SHAPE ABUTMENT ;
    PORT
      LAYER met2 ;
      RECT 205.090 655.100 205.230 655.520 ;
    END
  END rw0_rd_out[88]
  PIN rw0_rd_out[89]
    DIRECTION OUTPUT ;
    USE SIGNAL ;
    SHAPE ABUTMENT ;
    PORT
      LAYER met2 ;
      RECT 207.390 655.100 207.530 655.520 ;
    END
  END rw0_rd_out[89]
  PIN rw0_rd_out[90]
    DIRECTION OUTPUT ;
    USE SIGNAL ;
    SHAPE ABUTMENT ;
    PORT
      LAYER met2 ;
      RECT 209.690 655.100 209.830 655.520 ;
    END
  END rw0_rd_out[90]
  PIN rw0_rd_out[91]
    DIRECTION OUTPUT ;
    USE SIGNAL ;
    SHAPE ABUTMENT ;
    PORT
      LAYER met2 ;
      RECT 211.990 655.100 212.130 655.520 ;
    END
  END rw0_rd_out[91]
  PIN rw0_rd_out[92]
    DIRECTION OUTPUT ;
    USE SIGNAL ;
    SHAPE ABUTMENT ;
    PORT
      LAYER met2 ;
      RECT 214.290 655.100 214.430 655.520 ;
    END
  END rw0_rd_out[92]
  PIN rw0_rd_out[93]
    DIRECTION OUTPUT ;
    USE SIGNAL ;
    SHAPE ABUTMENT ;
    PORT
      LAYER met2 ;
      RECT 216.590 655.100 216.730 655.520 ;
    END
  END rw0_rd_out[93]
  PIN rw0_rd_out[94]
    DIRECTION OUTPUT ;
    USE SIGNAL ;
    SHAPE ABUTMENT ;
    PORT
      LAYER met2 ;
      RECT 218.890 655.100 219.030 655.520 ;
    END
  END rw0_rd_out[94]
  PIN rw0_rd_out[95]
    DIRECTION OUTPUT ;
    USE SIGNAL ;
    SHAPE ABUTMENT ;
    PORT
      LAYER met2 ;
      RECT 221.190 655.100 221.330 655.520 ;
    END
  END rw0_rd_out[95]
  PIN rw0_rd_out[96]
    DIRECTION OUTPUT ;
    USE SIGNAL ;
    SHAPE ABUTMENT ;
    PORT
      LAYER met2 ;
      RECT 223.490 655.100 223.630 655.520 ;
    END
  END rw0_rd_out[96]
  PIN rw0_rd_out[97]
    DIRECTION OUTPUT ;
    USE SIGNAL ;
    SHAPE ABUTMENT ;
    PORT
      LAYER met2 ;
      RECT 225.790 655.100 225.930 655.520 ;
    END
  END rw0_rd_out[97]
  PIN rw0_rd_out[98]
    DIRECTION OUTPUT ;
    USE SIGNAL ;
    SHAPE ABUTMENT ;
    PORT
      LAYER met2 ;
      RECT 228.090 655.100 228.230 655.520 ;
    END
  END rw0_rd_out[98]
  PIN rw0_rd_out[99]
    DIRECTION OUTPUT ;
    USE SIGNAL ;
    SHAPE ABUTMENT ;
    PORT
      LAYER met2 ;
      RECT 230.390 655.100 230.530 655.520 ;
    END
  END rw0_rd_out[99]
  PIN rw0_rd_out[100]
    DIRECTION OUTPUT ;
    USE SIGNAL ;
    SHAPE ABUTMENT ;
    PORT
      LAYER met2 ;
      RECT 232.690 655.100 232.830 655.520 ;
    END
  END rw0_rd_out[100]
  PIN rw0_rd_out[101]
    DIRECTION OUTPUT ;
    USE SIGNAL ;
    SHAPE ABUTMENT ;
    PORT
      LAYER met2 ;
      RECT 234.990 655.100 235.130 655.520 ;
    END
  END rw0_rd_out[101]
  PIN rw0_rd_out[102]
    DIRECTION OUTPUT ;
    USE SIGNAL ;
    SHAPE ABUTMENT ;
    PORT
      LAYER met2 ;
      RECT 237.290 655.100 237.430 655.520 ;
    END
  END rw0_rd_out[102]
  PIN rw0_rd_out[103]
    DIRECTION OUTPUT ;
    USE SIGNAL ;
    SHAPE ABUTMENT ;
    PORT
      LAYER met2 ;
      RECT 239.590 655.100 239.730 655.520 ;
    END
  END rw0_rd_out[103]
  PIN rw0_rd_out[104]
    DIRECTION OUTPUT ;
    USE SIGNAL ;
    SHAPE ABUTMENT ;
    PORT
      LAYER met2 ;
      RECT 241.890 655.100 242.030 655.520 ;
    END
  END rw0_rd_out[104]
  PIN rw0_rd_out[105]
    DIRECTION OUTPUT ;
    USE SIGNAL ;
    SHAPE ABUTMENT ;
    PORT
      LAYER met2 ;
      RECT 244.190 655.100 244.330 655.520 ;
    END
  END rw0_rd_out[105]
  PIN rw0_rd_out[106]
    DIRECTION OUTPUT ;
    USE SIGNAL ;
    SHAPE ABUTMENT ;
    PORT
      LAYER met2 ;
      RECT 246.490 655.100 246.630 655.520 ;
    END
  END rw0_rd_out[106]
  PIN rw0_rd_out[107]
    DIRECTION OUTPUT ;
    USE SIGNAL ;
    SHAPE ABUTMENT ;
    PORT
      LAYER met2 ;
      RECT 248.790 655.100 248.930 655.520 ;
    END
  END rw0_rd_out[107]
  PIN rw0_rd_out[108]
    DIRECTION OUTPUT ;
    USE SIGNAL ;
    SHAPE ABUTMENT ;
    PORT
      LAYER met2 ;
      RECT 251.090 655.100 251.230 655.520 ;
    END
  END rw0_rd_out[108]
  PIN rw0_rd_out[109]
    DIRECTION OUTPUT ;
    USE SIGNAL ;
    SHAPE ABUTMENT ;
    PORT
      LAYER met2 ;
      RECT 253.390 655.100 253.530 655.520 ;
    END
  END rw0_rd_out[109]
  PIN rw0_rd_out[110]
    DIRECTION OUTPUT ;
    USE SIGNAL ;
    SHAPE ABUTMENT ;
    PORT
      LAYER met2 ;
      RECT 255.690 655.100 255.830 655.520 ;
    END
  END rw0_rd_out[110]
  PIN rw0_rd_out[111]
    DIRECTION OUTPUT ;
    USE SIGNAL ;
    SHAPE ABUTMENT ;
    PORT
      LAYER met2 ;
      RECT 257.990 655.100 258.130 655.520 ;
    END
  END rw0_rd_out[111]
  PIN rw0_rd_out[112]
    DIRECTION OUTPUT ;
    USE SIGNAL ;
    SHAPE ABUTMENT ;
    PORT
      LAYER met2 ;
      RECT 260.290 655.100 260.430 655.520 ;
    END
  END rw0_rd_out[112]
  PIN rw0_rd_out[113]
    DIRECTION OUTPUT ;
    USE SIGNAL ;
    SHAPE ABUTMENT ;
    PORT
      LAYER met2 ;
      RECT 262.590 655.100 262.730 655.520 ;
    END
  END rw0_rd_out[113]
  PIN rw0_rd_out[114]
    DIRECTION OUTPUT ;
    USE SIGNAL ;
    SHAPE ABUTMENT ;
    PORT
      LAYER met2 ;
      RECT 264.890 655.100 265.030 655.520 ;
    END
  END rw0_rd_out[114]
  PIN rw0_rd_out[115]
    DIRECTION OUTPUT ;
    USE SIGNAL ;
    SHAPE ABUTMENT ;
    PORT
      LAYER met2 ;
      RECT 267.190 655.100 267.330 655.520 ;
    END
  END rw0_rd_out[115]
  PIN rw0_rd_out[116]
    DIRECTION OUTPUT ;
    USE SIGNAL ;
    SHAPE ABUTMENT ;
    PORT
      LAYER met2 ;
      RECT 269.490 655.100 269.630 655.520 ;
    END
  END rw0_rd_out[116]
  PIN rw0_rd_out[117]
    DIRECTION OUTPUT ;
    USE SIGNAL ;
    SHAPE ABUTMENT ;
    PORT
      LAYER met2 ;
      RECT 271.790 655.100 271.930 655.520 ;
    END
  END rw0_rd_out[117]
  PIN rw0_rd_out[118]
    DIRECTION OUTPUT ;
    USE SIGNAL ;
    SHAPE ABUTMENT ;
    PORT
      LAYER met2 ;
      RECT 274.090 655.100 274.230 655.520 ;
    END
  END rw0_rd_out[118]
  PIN rw0_rd_out[119]
    DIRECTION OUTPUT ;
    USE SIGNAL ;
    SHAPE ABUTMENT ;
    PORT
      LAYER met2 ;
      RECT 276.390 655.100 276.530 655.520 ;
    END
  END rw0_rd_out[119]
  PIN rw0_rd_out[120]
    DIRECTION OUTPUT ;
    USE SIGNAL ;
    SHAPE ABUTMENT ;
    PORT
      LAYER met2 ;
      RECT 278.690 655.100 278.830 655.520 ;
    END
  END rw0_rd_out[120]
  PIN rw0_rd_out[121]
    DIRECTION OUTPUT ;
    USE SIGNAL ;
    SHAPE ABUTMENT ;
    PORT
      LAYER met2 ;
      RECT 280.990 655.100 281.130 655.520 ;
    END
  END rw0_rd_out[121]
  PIN rw0_rd_out[122]
    DIRECTION OUTPUT ;
    USE SIGNAL ;
    SHAPE ABUTMENT ;
    PORT
      LAYER met2 ;
      RECT 283.290 655.100 283.430 655.520 ;
    END
  END rw0_rd_out[122]
  PIN rw0_rd_out[123]
    DIRECTION OUTPUT ;
    USE SIGNAL ;
    SHAPE ABUTMENT ;
    PORT
      LAYER met2 ;
      RECT 285.590 655.100 285.730 655.520 ;
    END
  END rw0_rd_out[123]
  PIN rw0_rd_out[124]
    DIRECTION OUTPUT ;
    USE SIGNAL ;
    SHAPE ABUTMENT ;
    PORT
      LAYER met2 ;
      RECT 287.890 655.100 288.030 655.520 ;
    END
  END rw0_rd_out[124]
  PIN rw0_rd_out[125]
    DIRECTION OUTPUT ;
    USE SIGNAL ;
    SHAPE ABUTMENT ;
    PORT
      LAYER met2 ;
      RECT 290.190 655.100 290.330 655.520 ;
    END
  END rw0_rd_out[125]
  PIN rw0_rd_out[126]
    DIRECTION OUTPUT ;
    USE SIGNAL ;
    SHAPE ABUTMENT ;
    PORT
      LAYER met2 ;
      RECT 292.490 655.100 292.630 655.520 ;
    END
  END rw0_rd_out[126]
  PIN rw0_rd_out[127]
    DIRECTION OUTPUT ;
    USE SIGNAL ;
    SHAPE ABUTMENT ;
    PORT
      LAYER met2 ;
      RECT 294.790 655.100 294.930 655.520 ;
    END
  END rw0_rd_out[127]
  PIN rw0_addr_in[0]
    DIRECTION INPUT ;
    USE SIGNAL ;
    SHAPE ABUTMENT ;
    PORT
      LAYER met3 ;
      RECT 0.000 569.690 0.900 569.990 ;
    END
  END rw0_addr_in[0]
  PIN rw0_addr_in[1]
    DIRECTION INPUT ;
    USE SIGNAL ;
    SHAPE ABUTMENT ;
    PORT
      LAYER met3 ;
      RECT 0.000 578.530 0.900 578.830 ;
    END
  END rw0_addr_in[1]
  PIN rw0_addr_in[2]
    DIRECTION INPUT ;
    USE SIGNAL ;
    SHAPE ABUTMENT ;
    PORT
      LAYER met3 ;
      RECT 0.000 587.370 0.900 587.670 ;
    END
  END rw0_addr_in[2]
  PIN rw0_addr_in[3]
    DIRECTION INPUT ;
    USE SIGNAL ;
    SHAPE ABUTMENT ;
    PORT
      LAYER met3 ;
      RECT 0.000 596.210 0.900 596.510 ;
    END
  END rw0_addr_in[3]
  PIN rw0_addr_in[4]
    DIRECTION INPUT ;
    USE SIGNAL ;
    SHAPE ABUTMENT ;
    PORT
      LAYER met3 ;
      RECT 352.840 569.690 353.740 569.990 ;
    END
  END rw0_addr_in[4]
  PIN rw0_addr_in[5]
    DIRECTION INPUT ;
    USE SIGNAL ;
    SHAPE ABUTMENT ;
    PORT
      LAYER met3 ;
      RECT 352.840 578.530 353.740 578.830 ;
    END
  END rw0_addr_in[5]
  PIN rw0_addr_in[6]
    DIRECTION INPUT ;
    USE SIGNAL ;
    SHAPE ABUTMENT ;
    PORT
      LAYER met3 ;
      RECT 352.840 587.370 353.740 587.670 ;
    END
  END rw0_addr_in[6]
  PIN rw0_addr_in[7]
    DIRECTION INPUT ;
    USE SIGNAL ;
    SHAPE ABUTMENT ;
    PORT
      LAYER met3 ;
      RECT 352.840 596.210 353.740 596.510 ;
    END
  END rw0_addr_in[7]
  PIN rw0_we_in
    DIRECTION INPUT ;
    USE SIGNAL ;
    SHAPE ABUTMENT ;
    PORT
      LAYER met2 ;
      RECT 297.090 655.100 297.230 655.520 ;
    END
  END rw0_we_in
  PIN rw0_ce_in
    DIRECTION INPUT ;
    USE SIGNAL ;
    SHAPE ABUTMENT ;
    PORT
      LAYER met2 ;
      RECT 299.390 655.100 299.530 655.520 ;
    END
  END rw0_ce_in
  PIN rw0_clk
    DIRECTION INPUT ;
    USE SIGNAL ;
    SHAPE ABUTMENT ;
    PORT
      LAYER met2 ;
      RECT 301.690 655.100 301.830 655.520 ;
    END
  END rw0_clk
  PIN VSS
    DIRECTION INOUT ;
    USE GROUND ;
    PORT
      LAYER met4 ;
      RECT 2.160 4.080 3.360 651.440 ;
      RECT 13.040 4.080 14.240 651.440 ;
      RECT 23.920 4.080 25.120 651.440 ;
      RECT 34.800 4.080 36.000 651.440 ;
      RECT 45.680 4.080 46.880 651.440 ;
      RECT 56.560 4.080 57.760 651.440 ;
      RECT 67.440 4.080 68.640 651.440 ;
      RECT 78.320 4.080 79.520 651.440 ;
      RECT 89.200 4.080 90.400 651.440 ;
      RECT 100.080 4.080 101.280 651.440 ;
      RECT 110.960 4.080 112.160 651.440 ;
      RECT 121.840 4.080 123.040 651.440 ;
      RECT 132.720 4.080 133.920 651.440 ;
      RECT 143.600 4.080 144.800 651.440 ;
      RECT 154.480 4.080 155.680 651.440 ;
      RECT 165.360 4.080 166.560 651.440 ;
      RECT 176.240 4.080 177.440 651.440 ;
      RECT 187.120 4.080 188.320 651.440 ;
      RECT 198.000 4.080 199.200 651.440 ;
      RECT 208.880 4.080 210.080 651.440 ;
      RECT 219.760 4.080 220.960 651.440 ;
      RECT 230.640 4.080 231.840 651.440 ;
      RECT 241.520 4.080 242.720 651.440 ;
      RECT 252.400 4.080 253.600 651.440 ;
      RECT 263.280 4.080 264.480 651.440 ;
      RECT 274.160 4.080 275.360 651.440 ;
      RECT 285.040 4.080 286.240 651.440 ;
      RECT 295.920 4.080 297.120 651.440 ;
      RECT 306.800 4.080 308.000 651.440 ;
      RECT 317.680 4.080 318.880 651.440 ;
      RECT 328.560 4.080 329.760 651.440 ;
      RECT 339.440 4.080 340.640 651.440 ;
      RECT 350.320 4.080 351.520 651.440 ;
    END
  END VSS
  PIN VDD
    DIRECTION INOUT ;
    USE POWER ;
    PORT
      LAYER met4 ;
      RECT 2.160 4.080 3.360 651.440 ;
      RECT 13.040 4.080 14.240 651.440 ;
      RECT 23.920 4.080 25.120 651.440 ;
      RECT 34.800 4.080 36.000 651.440 ;
      RECT 45.680 4.080 46.880 651.440 ;
      RECT 56.560 4.080 57.760 651.440 ;
      RECT 67.440 4.080 68.640 651.440 ;
      RECT 78.320 4.080 79.520 651.440 ;
      RECT 89.200 4.080 90.400 651.440 ;
      RECT 100.080 4.080 101.280 651.440 ;
      RECT 110.960 4.080 112.160 651.440 ;
      RECT 121.840 4.080 123.040 651.440 ;
      RECT 132.720 4.080 133.920 651.440 ;
      RECT 143.600 4.080 144.800 651.440 ;
      RECT 154.480 4.080 155.680 651.440 ;
      RECT 165.360 4.080 166.560 651.440 ;
      RECT 176.240 4.080 177.440 651.440 ;
      RECT 187.120 4.080 188.320 651.440 ;
      RECT 198.000 4.080 199.200 651.440 ;
      RECT 208.880 4.080 210.080 651.440 ;
      RECT 219.760 4.080 220.960 651.440 ;
      RECT 230.640 4.080 231.840 651.440 ;
      RECT 241.520 4.080 242.720 651.440 ;
      RECT 252.400 4.080 253.600 651.440 ;
      RECT 263.280 4.080 264.480 651.440 ;
      RECT 274.160 4.080 275.360 651.440 ;
      RECT 285.040 4.080 286.240 651.440 ;
      RECT 295.920 4.080 297.120 651.440 ;
      RECT 306.800 4.080 308.000 651.440 ;
      RECT 317.680 4.080 318.880 651.440 ;
      RECT 328.560 4.080 329.760 651.440 ;
      RECT 339.440 4.080 340.640 651.440 ;
      RECT 350.320 4.080 351.520 651.440 ;
    END
  END VDD
  OBS
    LAYER met1 ;
    RECT 0 0 353.740 655.520 ;
    LAYER met2 ;
    RECT 0 0 353.740 655.520 ;
    LAYER met3 ;
    RECT 0 0 353.740 655.520 ;
    LAYER met4 ;
    RECT 0 0 353.740 655.520 ;
  END
END fakeram_128x256_1rw

END LIBRARY
